VERSION 5.7 ;
BUSBITCHARS "[]" ;
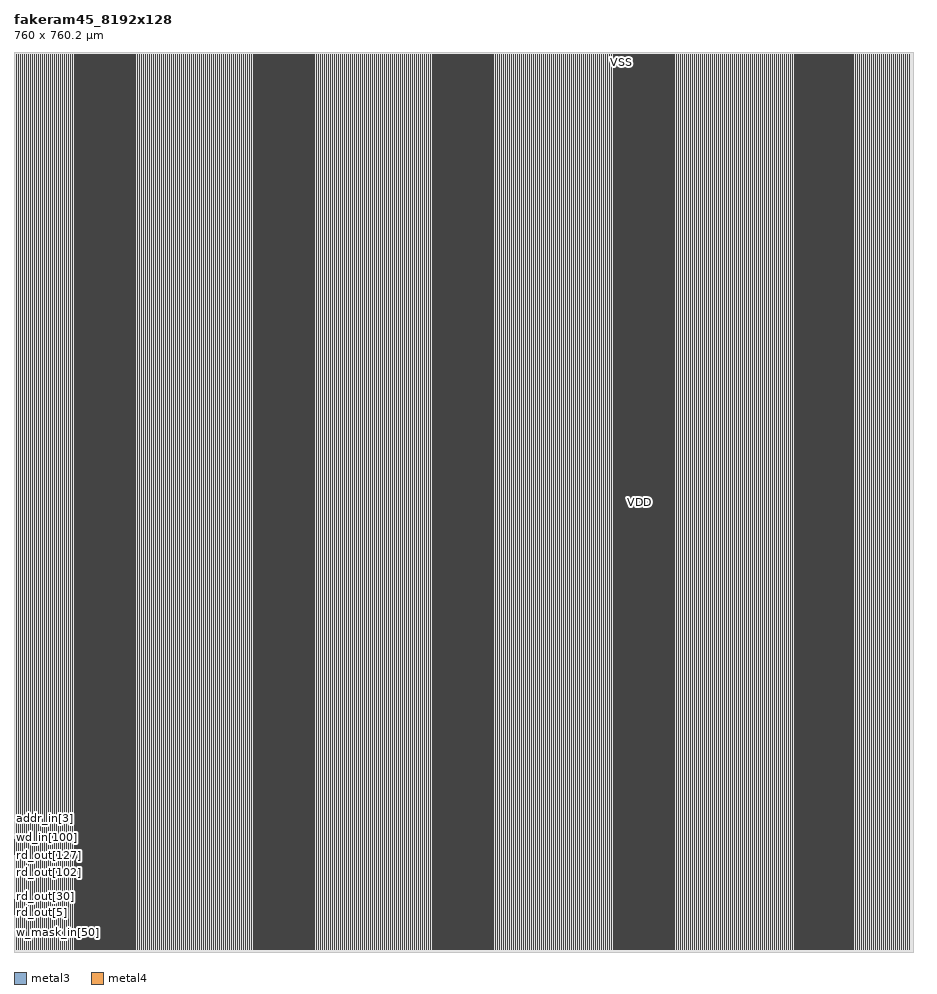
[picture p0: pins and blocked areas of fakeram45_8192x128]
MACRO fakeram45_8192x128
  FOREIGN fakeram45_8192x128 0 0 ;
  SYMMETRY X Y R90 ;
  SIZE 760.000 BY 760.200 ;
  CLASS BLOCK ;
  PIN w_mask_in[0]
    DIRECTION INPUT ;
    USE SIGNAL ;
    SHAPE ABUTMENT ;
    PORT
      LAYER metal3 ;
      RECT 0.000 2.135 0.070 2.205 ;
    END
  END w_mask_in[0]
  PIN w_mask_in[1]
    DIRECTION INPUT ;
    USE SIGNAL ;
    SHAPE ABUTMENT ;
    PORT
      LAYER metal3 ;
      RECT 0.000 2.415 0.070 2.485 ;
    END
  END w_mask_in[1]
  PIN w_mask_in[2]
    DIRECTION INPUT ;
    USE SIGNAL ;
    SHAPE ABUTMENT ;
    PORT
      LAYER metal3 ;
      RECT 0.000 2.695 0.070 2.765 ;
    END
  END w_mask_in[2]
  PIN w_mask_in[3]
    DIRECTION INPUT ;
    USE SIGNAL ;
    SHAPE ABUTMENT ;
    PORT
      LAYER metal3 ;
      RECT 0.000 2.975 0.070 3.045 ;
    END
  END w_mask_in[3]
  PIN w_mask_in[4]
    DIRECTION INPUT ;
    USE SIGNAL ;
    SHAPE ABUTMENT ;
    PORT
      LAYER metal3 ;
      RECT 0.000 3.255 0.070 3.325 ;
    END
  END w_mask_in[4]
  PIN w_mask_in[5]
    DIRECTION INPUT ;
    USE SIGNAL ;
    SHAPE ABUTMENT ;
    PORT
      LAYER metal3 ;
      RECT 0.000 3.535 0.070 3.605 ;
    END
  END w_mask_in[5]
  PIN w_mask_in[6]
    DIRECTION INPUT ;
    USE SIGNAL ;
    SHAPE ABUTMENT ;
    PORT
      LAYER metal3 ;
      RECT 0.000 3.815 0.070 3.885 ;
    END
  END w_mask_in[6]
  PIN w_mask_in[7]
    DIRECTION INPUT ;
    USE SIGNAL ;
    SHAPE ABUTMENT ;
    PORT
      LAYER metal3 ;
      RECT 0.000 4.095 0.070 4.165 ;
    END
  END w_mask_in[7]
  PIN w_mask_in[8]
    DIRECTION INPUT ;
    USE SIGNAL ;
    SHAPE ABUTMENT ;
    PORT
      LAYER metal3 ;
      RECT 0.000 4.375 0.070 4.445 ;
    END
  END w_mask_in[8]
  PIN w_mask_in[9]
    DIRECTION INPUT ;
    USE SIGNAL ;
    SHAPE ABUTMENT ;
    PORT
      LAYER metal3 ;
      RECT 0.000 4.655 0.070 4.725 ;
    END
  END w_mask_in[9]
  PIN w_mask_in[10]
    DIRECTION INPUT ;
    USE SIGNAL ;
    SHAPE ABUTMENT ;
    PORT
      LAYER metal3 ;
      RECT 0.000 4.935 0.070 5.005 ;
    END
  END w_mask_in[10]
  PIN w_mask_in[11]
    DIRECTION INPUT ;
    USE SIGNAL ;
    SHAPE ABUTMENT ;
    PORT
      LAYER metal3 ;
      RECT 0.000 5.215 0.070 5.285 ;
    END
  END w_mask_in[11]
  PIN w_mask_in[12]
    DIRECTION INPUT ;
    USE SIGNAL ;
    SHAPE ABUTMENT ;
    PORT
      LAYER metal3 ;
      RECT 0.000 5.495 0.070 5.565 ;
    END
  END w_mask_in[12]
  PIN w_mask_in[13]
    DIRECTION INPUT ;
    USE SIGNAL ;
    SHAPE ABUTMENT ;
    PORT
      LAYER metal3 ;
      RECT 0.000 5.775 0.070 5.845 ;
    END
  END w_mask_in[13]
  PIN w_mask_in[14]
    DIRECTION INPUT ;
    USE SIGNAL ;
    SHAPE ABUTMENT ;
    PORT
      LAYER metal3 ;
      RECT 0.000 6.055 0.070 6.125 ;
    END
  END w_mask_in[14]
  PIN w_mask_in[15]
    DIRECTION INPUT ;
    USE SIGNAL ;
    SHAPE ABUTMENT ;
    PORT
      LAYER metal3 ;
      RECT 0.000 6.335 0.070 6.405 ;
    END
  END w_mask_in[15]
  PIN w_mask_in[16]
    DIRECTION INPUT ;
    USE SIGNAL ;
    SHAPE ABUTMENT ;
    PORT
      LAYER metal3 ;
      RECT 0.000 6.615 0.070 6.685 ;
    END
  END w_mask_in[16]
  PIN w_mask_in[17]
    DIRECTION INPUT ;
    USE SIGNAL ;
    SHAPE ABUTMENT ;
    PORT
      LAYER metal3 ;
      RECT 0.000 6.895 0.070 6.965 ;
    END
  END w_mask_in[17]
  PIN w_mask_in[18]
    DIRECTION INPUT ;
    USE SIGNAL ;
    SHAPE ABUTMENT ;
    PORT
      LAYER metal3 ;
      RECT 0.000 7.175 0.070 7.245 ;
    END
  END w_mask_in[18]
  PIN w_mask_in[19]
    DIRECTION INPUT ;
    USE SIGNAL ;
    SHAPE ABUTMENT ;
    PORT
      LAYER metal3 ;
      RECT 0.000 7.455 0.070 7.525 ;
    END
  END w_mask_in[19]
  PIN w_mask_in[20]
    DIRECTION INPUT ;
    USE SIGNAL ;
    SHAPE ABUTMENT ;
    PORT
      LAYER metal3 ;
      RECT 0.000 7.735 0.070 7.805 ;
    END
  END w_mask_in[20]
  PIN w_mask_in[21]
    DIRECTION INPUT ;
    USE SIGNAL ;
    SHAPE ABUTMENT ;
    PORT
      LAYER metal3 ;
      RECT 0.000 8.015 0.070 8.085 ;
    END
  END w_mask_in[21]
  PIN w_mask_in[22]
    DIRECTION INPUT ;
    USE SIGNAL ;
    SHAPE ABUTMENT ;
    PORT
      LAYER metal3 ;
      RECT 0.000 8.295 0.070 8.365 ;
    END
  END w_mask_in[22]
  PIN w_mask_in[23]
    DIRECTION INPUT ;
    USE SIGNAL ;
    SHAPE ABUTMENT ;
    PORT
      LAYER metal3 ;
      RECT 0.000 8.575 0.070 8.645 ;
    END
  END w_mask_in[23]
  PIN w_mask_in[24]
    DIRECTION INPUT ;
    USE SIGNAL ;
    SHAPE ABUTMENT ;
    PORT
      LAYER metal3 ;
      RECT 0.000 8.855 0.070 8.925 ;
    END
  END w_mask_in[24]
  PIN w_mask_in[25]
    DIRECTION INPUT ;
    USE SIGNAL ;
    SHAPE ABUTMENT ;
    PORT
      LAYER metal3 ;
      RECT 0.000 9.135 0.070 9.205 ;
    END
  END w_mask_in[25]
  PIN w_mask_in[26]
    DIRECTION INPUT ;
    USE SIGNAL ;
    SHAPE ABUTMENT ;
    PORT
      LAYER metal3 ;
      RECT 0.000 9.415 0.070 9.485 ;
    END
  END w_mask_in[26]
  PIN w_mask_in[27]
    DIRECTION INPUT ;
    USE SIGNAL ;
    SHAPE ABUTMENT ;
    PORT
      LAYER metal3 ;
      RECT 0.000 9.695 0.070 9.765 ;
    END
  END w_mask_in[27]
  PIN w_mask_in[28]
    DIRECTION INPUT ;
    USE SIGNAL ;
    SHAPE ABUTMENT ;
    PORT
      LAYER metal3 ;
      RECT 0.000 9.975 0.070 10.045 ;
    END
  END w_mask_in[28]
  PIN w_mask_in[29]
    DIRECTION INPUT ;
    USE SIGNAL ;
    SHAPE ABUTMENT ;
    PORT
      LAYER metal3 ;
      RECT 0.000 10.255 0.070 10.325 ;
    END
  END w_mask_in[29]
  PIN w_mask_in[30]
    DIRECTION INPUT ;
    USE SIGNAL ;
    SHAPE ABUTMENT ;
    PORT
      LAYER metal3 ;
      RECT 0.000 10.535 0.070 10.605 ;
    END
  END w_mask_in[30]
  PIN w_mask_in[31]
    DIRECTION INPUT ;
    USE SIGNAL ;
    SHAPE ABUTMENT ;
    PORT
      LAYER metal3 ;
      RECT 0.000 10.815 0.070 10.885 ;
    END
  END w_mask_in[31]
  PIN w_mask_in[32]
    DIRECTION INPUT ;
    USE SIGNAL ;
    SHAPE ABUTMENT ;
    PORT
      LAYER metal3 ;
      RECT 0.000 11.095 0.070 11.165 ;
    END
  END w_mask_in[32]
  PIN w_mask_in[33]
    DIRECTION INPUT ;
    USE SIGNAL ;
    SHAPE ABUTMENT ;
    PORT
      LAYER metal3 ;
      RECT 0.000 11.375 0.070 11.445 ;
    END
  END w_mask_in[33]
  PIN w_mask_in[34]
    DIRECTION INPUT ;
    USE SIGNAL ;
    SHAPE ABUTMENT ;
    PORT
      LAYER metal3 ;
      RECT 0.000 11.655 0.070 11.725 ;
    END
  END w_mask_in[34]
  PIN w_mask_in[35]
    DIRECTION INPUT ;
    USE SIGNAL ;
    SHAPE ABUTMENT ;
    PORT
      LAYER metal3 ;
      RECT 0.000 11.935 0.070 12.005 ;
    END
  END w_mask_in[35]
  PIN w_mask_in[36]
    DIRECTION INPUT ;
    USE SIGNAL ;
    SHAPE ABUTMENT ;
    PORT
      LAYER metal3 ;
      RECT 0.000 12.215 0.070 12.285 ;
    END
  END w_mask_in[36]
  PIN w_mask_in[37]
    DIRECTION INPUT ;
    USE SIGNAL ;
    SHAPE ABUTMENT ;
    PORT
      LAYER metal3 ;
      RECT 0.000 12.495 0.070 12.565 ;
    END
  END w_mask_in[37]
  PIN w_mask_in[38]
    DIRECTION INPUT ;
    USE SIGNAL ;
    SHAPE ABUTMENT ;
    PORT
      LAYER metal3 ;
      RECT 0.000 12.775 0.070 12.845 ;
    END
  END w_mask_in[38]
  PIN w_mask_in[39]
    DIRECTION INPUT ;
    USE SIGNAL ;
    SHAPE ABUTMENT ;
    PORT
      LAYER metal3 ;
      RECT 0.000 13.055 0.070 13.125 ;
    END
  END w_mask_in[39]
  PIN w_mask_in[40]
    DIRECTION INPUT ;
    USE SIGNAL ;
    SHAPE ABUTMENT ;
    PORT
      LAYER metal3 ;
      RECT 0.000 13.335 0.070 13.405 ;
    END
  END w_mask_in[40]
  PIN w_mask_in[41]
    DIRECTION INPUT ;
    USE SIGNAL ;
    SHAPE ABUTMENT ;
    PORT
      LAYER metal3 ;
      RECT 0.000 13.615 0.070 13.685 ;
    END
  END w_mask_in[41]
  PIN w_mask_in[42]
    DIRECTION INPUT ;
    USE SIGNAL ;
    SHAPE ABUTMENT ;
    PORT
      LAYER metal3 ;
      RECT 0.000 13.895 0.070 13.965 ;
    END
  END w_mask_in[42]
  PIN w_mask_in[43]
    DIRECTION INPUT ;
    USE SIGNAL ;
    SHAPE ABUTMENT ;
    PORT
      LAYER metal3 ;
      RECT 0.000 14.175 0.070 14.245 ;
    END
  END w_mask_in[43]
  PIN w_mask_in[44]
    DIRECTION INPUT ;
    USE SIGNAL ;
    SHAPE ABUTMENT ;
    PORT
      LAYER metal3 ;
      RECT 0.000 14.455 0.070 14.525 ;
    END
  END w_mask_in[44]
  PIN w_mask_in[45]
    DIRECTION INPUT ;
    USE SIGNAL ;
    SHAPE ABUTMENT ;
    PORT
      LAYER metal3 ;
      RECT 0.000 14.735 0.070 14.805 ;
    END
  END w_mask_in[45]
  PIN w_mask_in[46]
    DIRECTION INPUT ;
    USE SIGNAL ;
    SHAPE ABUTMENT ;
    PORT
      LAYER metal3 ;
      RECT 0.000 15.015 0.070 15.085 ;
    END
  END w_mask_in[46]
  PIN w_mask_in[47]
    DIRECTION INPUT ;
    USE SIGNAL ;
    SHAPE ABUTMENT ;
    PORT
      LAYER metal3 ;
      RECT 0.000 15.295 0.070 15.365 ;
    END
  END w_mask_in[47]
  PIN w_mask_in[48]
    DIRECTION INPUT ;
    USE SIGNAL ;
    SHAPE ABUTMENT ;
    PORT
      LAYER metal3 ;
      RECT 0.000 15.575 0.070 15.645 ;
    END
  END w_mask_in[48]
  PIN w_mask_in[49]
    DIRECTION INPUT ;
    USE SIGNAL ;
    SHAPE ABUTMENT ;
    PORT
      LAYER metal3 ;
      RECT 0.000 15.855 0.070 15.925 ;
    END
  END w_mask_in[49]
  PIN w_mask_in[50]
    DIRECTION INPUT ;
    USE SIGNAL ;
    SHAPE ABUTMENT ;
    PORT
      LAYER metal3 ;
      RECT 0.000 16.135 0.070 16.205 ;
    END
  END w_mask_in[50]
  PIN w_mask_in[51]
    DIRECTION INPUT ;
    USE SIGNAL ;
    SHAPE ABUTMENT ;
    PORT
      LAYER metal3 ;
      RECT 0.000 16.415 0.070 16.485 ;
    END
  END w_mask_in[51]
  PIN w_mask_in[52]
    DIRECTION INPUT ;
    USE SIGNAL ;
    SHAPE ABUTMENT ;
    PORT
      LAYER metal3 ;
      RECT 0.000 16.695 0.070 16.765 ;
    END
  END w_mask_in[52]
  PIN w_mask_in[53]
    DIRECTION INPUT ;
    USE SIGNAL ;
    SHAPE ABUTMENT ;
    PORT
      LAYER metal3 ;
      RECT 0.000 16.975 0.070 17.045 ;
    END
  END w_mask_in[53]
  PIN w_mask_in[54]
    DIRECTION INPUT ;
    USE SIGNAL ;
    SHAPE ABUTMENT ;
    PORT
      LAYER metal3 ;
      RECT 0.000 17.255 0.070 17.325 ;
    END
  END w_mask_in[54]
  PIN w_mask_in[55]
    DIRECTION INPUT ;
    USE SIGNAL ;
    SHAPE ABUTMENT ;
    PORT
      LAYER metal3 ;
      RECT 0.000 17.535 0.070 17.605 ;
    END
  END w_mask_in[55]
  PIN w_mask_in[56]
    DIRECTION INPUT ;
    USE SIGNAL ;
    SHAPE ABUTMENT ;
    PORT
      LAYER metal3 ;
      RECT 0.000 17.815 0.070 17.885 ;
    END
  END w_mask_in[56]
  PIN w_mask_in[57]
    DIRECTION INPUT ;
    USE SIGNAL ;
    SHAPE ABUTMENT ;
    PORT
      LAYER metal3 ;
      RECT 0.000 18.095 0.070 18.165 ;
    END
  END w_mask_in[57]
  PIN w_mask_in[58]
    DIRECTION INPUT ;
    USE SIGNAL ;
    SHAPE ABUTMENT ;
    PORT
      LAYER metal3 ;
      RECT 0.000 18.375 0.070 18.445 ;
    END
  END w_mask_in[58]
  PIN w_mask_in[59]
    DIRECTION INPUT ;
    USE SIGNAL ;
    SHAPE ABUTMENT ;
    PORT
      LAYER metal3 ;
      RECT 0.000 18.655 0.070 18.725 ;
    END
  END w_mask_in[59]
  PIN w_mask_in[60]
    DIRECTION INPUT ;
    USE SIGNAL ;
    SHAPE ABUTMENT ;
    PORT
      LAYER metal3 ;
      RECT 0.000 18.935 0.070 19.005 ;
    END
  END w_mask_in[60]
  PIN w_mask_in[61]
    DIRECTION INPUT ;
    USE SIGNAL ;
    SHAPE ABUTMENT ;
    PORT
      LAYER metal3 ;
      RECT 0.000 19.215 0.070 19.285 ;
    END
  END w_mask_in[61]
  PIN w_mask_in[62]
    DIRECTION INPUT ;
    USE SIGNAL ;
    SHAPE ABUTMENT ;
    PORT
      LAYER metal3 ;
      RECT 0.000 19.495 0.070 19.565 ;
    END
  END w_mask_in[62]
  PIN w_mask_in[63]
    DIRECTION INPUT ;
    USE SIGNAL ;
    SHAPE ABUTMENT ;
    PORT
      LAYER metal3 ;
      RECT 0.000 19.775 0.070 19.845 ;
    END
  END w_mask_in[63]
  PIN w_mask_in[64]
    DIRECTION INPUT ;
    USE SIGNAL ;
    SHAPE ABUTMENT ;
    PORT
      LAYER metal3 ;
      RECT 0.000 20.055 0.070 20.125 ;
    END
  END w_mask_in[64]
  PIN w_mask_in[65]
    DIRECTION INPUT ;
    USE SIGNAL ;
    SHAPE ABUTMENT ;
    PORT
      LAYER metal3 ;
      RECT 0.000 20.335 0.070 20.405 ;
    END
  END w_mask_in[65]
  PIN w_mask_in[66]
    DIRECTION INPUT ;
    USE SIGNAL ;
    SHAPE ABUTMENT ;
    PORT
      LAYER metal3 ;
      RECT 0.000 20.615 0.070 20.685 ;
    END
  END w_mask_in[66]
  PIN w_mask_in[67]
    DIRECTION INPUT ;
    USE SIGNAL ;
    SHAPE ABUTMENT ;
    PORT
      LAYER metal3 ;
      RECT 0.000 20.895 0.070 20.965 ;
    END
  END w_mask_in[67]
  PIN w_mask_in[68]
    DIRECTION INPUT ;
    USE SIGNAL ;
    SHAPE ABUTMENT ;
    PORT
      LAYER metal3 ;
      RECT 0.000 21.175 0.070 21.245 ;
    END
  END w_mask_in[68]
  PIN w_mask_in[69]
    DIRECTION INPUT ;
    USE SIGNAL ;
    SHAPE ABUTMENT ;
    PORT
      LAYER metal3 ;
      RECT 0.000 21.455 0.070 21.525 ;
    END
  END w_mask_in[69]
  PIN w_mask_in[70]
    DIRECTION INPUT ;
    USE SIGNAL ;
    SHAPE ABUTMENT ;
    PORT
      LAYER metal3 ;
      RECT 0.000 21.735 0.070 21.805 ;
    END
  END w_mask_in[70]
  PIN w_mask_in[71]
    DIRECTION INPUT ;
    USE SIGNAL ;
    SHAPE ABUTMENT ;
    PORT
      LAYER metal3 ;
      RECT 0.000 22.015 0.070 22.085 ;
    END
  END w_mask_in[71]
  PIN w_mask_in[72]
    DIRECTION INPUT ;
    USE SIGNAL ;
    SHAPE ABUTMENT ;
    PORT
      LAYER metal3 ;
      RECT 0.000 22.295 0.070 22.365 ;
    END
  END w_mask_in[72]
  PIN w_mask_in[73]
    DIRECTION INPUT ;
    USE SIGNAL ;
    SHAPE ABUTMENT ;
    PORT
      LAYER metal3 ;
      RECT 0.000 22.575 0.070 22.645 ;
    END
  END w_mask_in[73]
  PIN w_mask_in[74]
    DIRECTION INPUT ;
    USE SIGNAL ;
    SHAPE ABUTMENT ;
    PORT
      LAYER metal3 ;
      RECT 0.000 22.855 0.070 22.925 ;
    END
  END w_mask_in[74]
  PIN w_mask_in[75]
    DIRECTION INPUT ;
    USE SIGNAL ;
    SHAPE ABUTMENT ;
    PORT
      LAYER metal3 ;
      RECT 0.000 23.135 0.070 23.205 ;
    END
  END w_mask_in[75]
  PIN w_mask_in[76]
    DIRECTION INPUT ;
    USE SIGNAL ;
    SHAPE ABUTMENT ;
    PORT
      LAYER metal3 ;
      RECT 0.000 23.415 0.070 23.485 ;
    END
  END w_mask_in[76]
  PIN w_mask_in[77]
    DIRECTION INPUT ;
    USE SIGNAL ;
    SHAPE ABUTMENT ;
    PORT
      LAYER metal3 ;
      RECT 0.000 23.695 0.070 23.765 ;
    END
  END w_mask_in[77]
  PIN w_mask_in[78]
    DIRECTION INPUT ;
    USE SIGNAL ;
    SHAPE ABUTMENT ;
    PORT
      LAYER metal3 ;
      RECT 0.000 23.975 0.070 24.045 ;
    END
  END w_mask_in[78]
  PIN w_mask_in[79]
    DIRECTION INPUT ;
    USE SIGNAL ;
    SHAPE ABUTMENT ;
    PORT
      LAYER metal3 ;
      RECT 0.000 24.255 0.070 24.325 ;
    END
  END w_mask_in[79]
  PIN w_mask_in[80]
    DIRECTION INPUT ;
    USE SIGNAL ;
    SHAPE ABUTMENT ;
    PORT
      LAYER metal3 ;
      RECT 0.000 24.535 0.070 24.605 ;
    END
  END w_mask_in[80]
  PIN w_mask_in[81]
    DIRECTION INPUT ;
    USE SIGNAL ;
    SHAPE ABUTMENT ;
    PORT
      LAYER metal3 ;
      RECT 0.000 24.815 0.070 24.885 ;
    END
  END w_mask_in[81]
  PIN w_mask_in[82]
    DIRECTION INPUT ;
    USE SIGNAL ;
    SHAPE ABUTMENT ;
    PORT
      LAYER metal3 ;
      RECT 0.000 25.095 0.070 25.165 ;
    END
  END w_mask_in[82]
  PIN w_mask_in[83]
    DIRECTION INPUT ;
    USE SIGNAL ;
    SHAPE ABUTMENT ;
    PORT
      LAYER metal3 ;
      RECT 0.000 25.375 0.070 25.445 ;
    END
  END w_mask_in[83]
  PIN w_mask_in[84]
    DIRECTION INPUT ;
    USE SIGNAL ;
    SHAPE ABUTMENT ;
    PORT
      LAYER metal3 ;
      RECT 0.000 25.655 0.070 25.725 ;
    END
  END w_mask_in[84]
  PIN w_mask_in[85]
    DIRECTION INPUT ;
    USE SIGNAL ;
    SHAPE ABUTMENT ;
    PORT
      LAYER metal3 ;
      RECT 0.000 25.935 0.070 26.005 ;
    END
  END w_mask_in[85]
  PIN w_mask_in[86]
    DIRECTION INPUT ;
    USE SIGNAL ;
    SHAPE ABUTMENT ;
    PORT
      LAYER metal3 ;
      RECT 0.000 26.215 0.070 26.285 ;
    END
  END w_mask_in[86]
  PIN w_mask_in[87]
    DIRECTION INPUT ;
    USE SIGNAL ;
    SHAPE ABUTMENT ;
    PORT
      LAYER metal3 ;
      RECT 0.000 26.495 0.070 26.565 ;
    END
  END w_mask_in[87]
  PIN w_mask_in[88]
    DIRECTION INPUT ;
    USE SIGNAL ;
    SHAPE ABUTMENT ;
    PORT
      LAYER metal3 ;
      RECT 0.000 26.775 0.070 26.845 ;
    END
  END w_mask_in[88]
  PIN w_mask_in[89]
    DIRECTION INPUT ;
    USE SIGNAL ;
    SHAPE ABUTMENT ;
    PORT
      LAYER metal3 ;
      RECT 0.000 27.055 0.070 27.125 ;
    END
  END w_mask_in[89]
  PIN w_mask_in[90]
    DIRECTION INPUT ;
    USE SIGNAL ;
    SHAPE ABUTMENT ;
    PORT
      LAYER metal3 ;
      RECT 0.000 27.335 0.070 27.405 ;
    END
  END w_mask_in[90]
  PIN w_mask_in[91]
    DIRECTION INPUT ;
    USE SIGNAL ;
    SHAPE ABUTMENT ;
    PORT
      LAYER metal3 ;
      RECT 0.000 27.615 0.070 27.685 ;
    END
  END w_mask_in[91]
  PIN w_mask_in[92]
    DIRECTION INPUT ;
    USE SIGNAL ;
    SHAPE ABUTMENT ;
    PORT
      LAYER metal3 ;
      RECT 0.000 27.895 0.070 27.965 ;
    END
  END w_mask_in[92]
  PIN w_mask_in[93]
    DIRECTION INPUT ;
    USE SIGNAL ;
    SHAPE ABUTMENT ;
    PORT
      LAYER metal3 ;
      RECT 0.000 28.175 0.070 28.245 ;
    END
  END w_mask_in[93]
  PIN w_mask_in[94]
    DIRECTION INPUT ;
    USE SIGNAL ;
    SHAPE ABUTMENT ;
    PORT
      LAYER metal3 ;
      RECT 0.000 28.455 0.070 28.525 ;
    END
  END w_mask_in[94]
  PIN w_mask_in[95]
    DIRECTION INPUT ;
    USE SIGNAL ;
    SHAPE ABUTMENT ;
    PORT
      LAYER metal3 ;
      RECT 0.000 28.735 0.070 28.805 ;
    END
  END w_mask_in[95]
  PIN w_mask_in[96]
    DIRECTION INPUT ;
    USE SIGNAL ;
    SHAPE ABUTMENT ;
    PORT
      LAYER metal3 ;
      RECT 0.000 29.015 0.070 29.085 ;
    END
  END w_mask_in[96]
  PIN w_mask_in[97]
    DIRECTION INPUT ;
    USE SIGNAL ;
    SHAPE ABUTMENT ;
    PORT
      LAYER metal3 ;
      RECT 0.000 29.295 0.070 29.365 ;
    END
  END w_mask_in[97]
  PIN w_mask_in[98]
    DIRECTION INPUT ;
    USE SIGNAL ;
    SHAPE ABUTMENT ;
    PORT
      LAYER metal3 ;
      RECT 0.000 29.575 0.070 29.645 ;
    END
  END w_mask_in[98]
  PIN w_mask_in[99]
    DIRECTION INPUT ;
    USE SIGNAL ;
    SHAPE ABUTMENT ;
    PORT
      LAYER metal3 ;
      RECT 0.000 29.855 0.070 29.925 ;
    END
  END w_mask_in[99]
  PIN w_mask_in[100]
    DIRECTION INPUT ;
    USE SIGNAL ;
    SHAPE ABUTMENT ;
    PORT
      LAYER metal3 ;
      RECT 0.000 30.135 0.070 30.205 ;
    END
  END w_mask_in[100]
  PIN w_mask_in[101]
    DIRECTION INPUT ;
    USE SIGNAL ;
    SHAPE ABUTMENT ;
    PORT
      LAYER metal3 ;
      RECT 0.000 30.415 0.070 30.485 ;
    END
  END w_mask_in[101]
  PIN w_mask_in[102]
    DIRECTION INPUT ;
    USE SIGNAL ;
    SHAPE ABUTMENT ;
    PORT
      LAYER metal3 ;
      RECT 0.000 30.695 0.070 30.765 ;
    END
  END w_mask_in[102]
  PIN w_mask_in[103]
    DIRECTION INPUT ;
    USE SIGNAL ;
    SHAPE ABUTMENT ;
    PORT
      LAYER metal3 ;
      RECT 0.000 30.975 0.070 31.045 ;
    END
  END w_mask_in[103]
  PIN w_mask_in[104]
    DIRECTION INPUT ;
    USE SIGNAL ;
    SHAPE ABUTMENT ;
    PORT
      LAYER metal3 ;
      RECT 0.000 31.255 0.070 31.325 ;
    END
  END w_mask_in[104]
  PIN w_mask_in[105]
    DIRECTION INPUT ;
    USE SIGNAL ;
    SHAPE ABUTMENT ;
    PORT
      LAYER metal3 ;
      RECT 0.000 31.535 0.070 31.605 ;
    END
  END w_mask_in[105]
  PIN w_mask_in[106]
    DIRECTION INPUT ;
    USE SIGNAL ;
    SHAPE ABUTMENT ;
    PORT
      LAYER metal3 ;
      RECT 0.000 31.815 0.070 31.885 ;
    END
  END w_mask_in[106]
  PIN w_mask_in[107]
    DIRECTION INPUT ;
    USE SIGNAL ;
    SHAPE ABUTMENT ;
    PORT
      LAYER metal3 ;
      RECT 0.000 32.095 0.070 32.165 ;
    END
  END w_mask_in[107]
  PIN w_mask_in[108]
    DIRECTION INPUT ;
    USE SIGNAL ;
    SHAPE ABUTMENT ;
    PORT
      LAYER metal3 ;
      RECT 0.000 32.375 0.070 32.445 ;
    END
  END w_mask_in[108]
  PIN w_mask_in[109]
    DIRECTION INPUT ;
    USE SIGNAL ;
    SHAPE ABUTMENT ;
    PORT
      LAYER metal3 ;
      RECT 0.000 32.655 0.070 32.725 ;
    END
  END w_mask_in[109]
  PIN w_mask_in[110]
    DIRECTION INPUT ;
    USE SIGNAL ;
    SHAPE ABUTMENT ;
    PORT
      LAYER metal3 ;
      RECT 0.000 32.935 0.070 33.005 ;
    END
  END w_mask_in[110]
  PIN w_mask_in[111]
    DIRECTION INPUT ;
    USE SIGNAL ;
    SHAPE ABUTMENT ;
    PORT
      LAYER metal3 ;
      RECT 0.000 33.215 0.070 33.285 ;
    END
  END w_mask_in[111]
  PIN w_mask_in[112]
    DIRECTION INPUT ;
    USE SIGNAL ;
    SHAPE ABUTMENT ;
    PORT
      LAYER metal3 ;
      RECT 0.000 33.495 0.070 33.565 ;
    END
  END w_mask_in[112]
  PIN w_mask_in[113]
    DIRECTION INPUT ;
    USE SIGNAL ;
    SHAPE ABUTMENT ;
    PORT
      LAYER metal3 ;
      RECT 0.000 33.775 0.070 33.845 ;
    END
  END w_mask_in[113]
  PIN w_mask_in[114]
    DIRECTION INPUT ;
    USE SIGNAL ;
    SHAPE ABUTMENT ;
    PORT
      LAYER metal3 ;
      RECT 0.000 34.055 0.070 34.125 ;
    END
  END w_mask_in[114]
  PIN w_mask_in[115]
    DIRECTION INPUT ;
    USE SIGNAL ;
    SHAPE ABUTMENT ;
    PORT
      LAYER metal3 ;
      RECT 0.000 34.335 0.070 34.405 ;
    END
  END w_mask_in[115]
  PIN w_mask_in[116]
    DIRECTION INPUT ;
    USE SIGNAL ;
    SHAPE ABUTMENT ;
    PORT
      LAYER metal3 ;
      RECT 0.000 34.615 0.070 34.685 ;
    END
  END w_mask_in[116]
  PIN w_mask_in[117]
    DIRECTION INPUT ;
    USE SIGNAL ;
    SHAPE ABUTMENT ;
    PORT
      LAYER metal3 ;
      RECT 0.000 34.895 0.070 34.965 ;
    END
  END w_mask_in[117]
  PIN w_mask_in[118]
    DIRECTION INPUT ;
    USE SIGNAL ;
    SHAPE ABUTMENT ;
    PORT
      LAYER metal3 ;
      RECT 0.000 35.175 0.070 35.245 ;
    END
  END w_mask_in[118]
  PIN w_mask_in[119]
    DIRECTION INPUT ;
    USE SIGNAL ;
    SHAPE ABUTMENT ;
    PORT
      LAYER metal3 ;
      RECT 0.000 35.455 0.070 35.525 ;
    END
  END w_mask_in[119]
  PIN w_mask_in[120]
    DIRECTION INPUT ;
    USE SIGNAL ;
    SHAPE ABUTMENT ;
    PORT
      LAYER metal3 ;
      RECT 0.000 35.735 0.070 35.805 ;
    END
  END w_mask_in[120]
  PIN w_mask_in[121]
    DIRECTION INPUT ;
    USE SIGNAL ;
    SHAPE ABUTMENT ;
    PORT
      LAYER metal3 ;
      RECT 0.000 36.015 0.070 36.085 ;
    END
  END w_mask_in[121]
  PIN w_mask_in[122]
    DIRECTION INPUT ;
    USE SIGNAL ;
    SHAPE ABUTMENT ;
    PORT
      LAYER metal3 ;
      RECT 0.000 36.295 0.070 36.365 ;
    END
  END w_mask_in[122]
  PIN w_mask_in[123]
    DIRECTION INPUT ;
    USE SIGNAL ;
    SHAPE ABUTMENT ;
    PORT
      LAYER metal3 ;
      RECT 0.000 36.575 0.070 36.645 ;
    END
  END w_mask_in[123]
  PIN w_mask_in[124]
    DIRECTION INPUT ;
    USE SIGNAL ;
    SHAPE ABUTMENT ;
    PORT
      LAYER metal3 ;
      RECT 0.000 36.855 0.070 36.925 ;
    END
  END w_mask_in[124]
  PIN w_mask_in[125]
    DIRECTION INPUT ;
    USE SIGNAL ;
    SHAPE ABUTMENT ;
    PORT
      LAYER metal3 ;
      RECT 0.000 37.135 0.070 37.205 ;
    END
  END w_mask_in[125]
  PIN w_mask_in[126]
    DIRECTION INPUT ;
    USE SIGNAL ;
    SHAPE ABUTMENT ;
    PORT
      LAYER metal3 ;
      RECT 0.000 37.415 0.070 37.485 ;
    END
  END w_mask_in[126]
  PIN w_mask_in[127]
    DIRECTION INPUT ;
    USE SIGNAL ;
    SHAPE ABUTMENT ;
    PORT
      LAYER metal3 ;
      RECT 0.000 37.695 0.070 37.765 ;
    END
  END w_mask_in[127]
  PIN rd_out[0]
    DIRECTION OUTPUT ;
    USE SIGNAL ;
    SHAPE ABUTMENT ;
    PORT
      LAYER metal3 ;
      RECT 0.000 38.815 0.070 38.885 ;
    END
  END rd_out[0]
  PIN rd_out[1]
    DIRECTION OUTPUT ;
    USE SIGNAL ;
    SHAPE ABUTMENT ;
    PORT
      LAYER metal3 ;
      RECT 0.000 39.095 0.070 39.165 ;
    END
  END rd_out[1]
  PIN rd_out[2]
    DIRECTION OUTPUT ;
    USE SIGNAL ;
    SHAPE ABUTMENT ;
    PORT
      LAYER metal3 ;
      RECT 0.000 39.375 0.070 39.445 ;
    END
  END rd_out[2]
  PIN rd_out[3]
    DIRECTION OUTPUT ;
    USE SIGNAL ;
    SHAPE ABUTMENT ;
    PORT
      LAYER metal3 ;
      RECT 0.000 39.655 0.070 39.725 ;
    END
  END rd_out[3]
  PIN rd_out[4]
    DIRECTION OUTPUT ;
    USE SIGNAL ;
    SHAPE ABUTMENT ;
    PORT
      LAYER metal3 ;
      RECT 0.000 39.935 0.070 40.005 ;
    END
  END rd_out[4]
  PIN rd_out[5]
    DIRECTION OUTPUT ;
    USE SIGNAL ;
    SHAPE ABUTMENT ;
    PORT
      LAYER metal3 ;
      RECT 0.000 40.215 0.070 40.285 ;
    END
  END rd_out[5]
  PIN rd_out[6]
    DIRECTION OUTPUT ;
    USE SIGNAL ;
    SHAPE ABUTMENT ;
    PORT
      LAYER metal3 ;
      RECT 0.000 40.495 0.070 40.565 ;
    END
  END rd_out[6]
  PIN rd_out[7]
    DIRECTION OUTPUT ;
    USE SIGNAL ;
    SHAPE ABUTMENT ;
    PORT
      LAYER metal3 ;
      RECT 0.000 40.775 0.070 40.845 ;
    END
  END rd_out[7]
  PIN rd_out[8]
    DIRECTION OUTPUT ;
    USE SIGNAL ;
    SHAPE ABUTMENT ;
    PORT
      LAYER metal3 ;
      RECT 0.000 41.055 0.070 41.125 ;
    END
  END rd_out[8]
  PIN rd_out[9]
    DIRECTION OUTPUT ;
    USE SIGNAL ;
    SHAPE ABUTMENT ;
    PORT
      LAYER metal3 ;
      RECT 0.000 41.335 0.070 41.405 ;
    END
  END rd_out[9]
  PIN rd_out[10]
    DIRECTION OUTPUT ;
    USE SIGNAL ;
    SHAPE ABUTMENT ;
    PORT
      LAYER metal3 ;
      RECT 0.000 41.615 0.070 41.685 ;
    END
  END rd_out[10]
  PIN rd_out[11]
    DIRECTION OUTPUT ;
    USE SIGNAL ;
    SHAPE ABUTMENT ;
    PORT
      LAYER metal3 ;
      RECT 0.000 41.895 0.070 41.965 ;
    END
  END rd_out[11]
  PIN rd_out[12]
    DIRECTION OUTPUT ;
    USE SIGNAL ;
    SHAPE ABUTMENT ;
    PORT
      LAYER metal3 ;
      RECT 0.000 42.175 0.070 42.245 ;
    END
  END rd_out[12]
  PIN rd_out[13]
    DIRECTION OUTPUT ;
    USE SIGNAL ;
    SHAPE ABUTMENT ;
    PORT
      LAYER metal3 ;
      RECT 0.000 42.455 0.070 42.525 ;
    END
  END rd_out[13]
  PIN rd_out[14]
    DIRECTION OUTPUT ;
    USE SIGNAL ;
    SHAPE ABUTMENT ;
    PORT
      LAYER metal3 ;
      RECT 0.000 42.735 0.070 42.805 ;
    END
  END rd_out[14]
  PIN rd_out[15]
    DIRECTION OUTPUT ;
    USE SIGNAL ;
    SHAPE ABUTMENT ;
    PORT
      LAYER metal3 ;
      RECT 0.000 43.015 0.070 43.085 ;
    END
  END rd_out[15]
  PIN rd_out[16]
    DIRECTION OUTPUT ;
    USE SIGNAL ;
    SHAPE ABUTMENT ;
    PORT
      LAYER metal3 ;
      RECT 0.000 43.295 0.070 43.365 ;
    END
  END rd_out[16]
  PIN rd_out[17]
    DIRECTION OUTPUT ;
    USE SIGNAL ;
    SHAPE ABUTMENT ;
    PORT
      LAYER metal3 ;
      RECT 0.000 43.575 0.070 43.645 ;
    END
  END rd_out[17]
  PIN rd_out[18]
    DIRECTION OUTPUT ;
    USE SIGNAL ;
    SHAPE ABUTMENT ;
    PORT
      LAYER metal3 ;
      RECT 0.000 43.855 0.070 43.925 ;
    END
  END rd_out[18]
  PIN rd_out[19]
    DIRECTION OUTPUT ;
    USE SIGNAL ;
    SHAPE ABUTMENT ;
    PORT
      LAYER metal3 ;
      RECT 0.000 44.135 0.070 44.205 ;
    END
  END rd_out[19]
  PIN rd_out[20]
    DIRECTION OUTPUT ;
    USE SIGNAL ;
    SHAPE ABUTMENT ;
    PORT
      LAYER metal3 ;
      RECT 0.000 44.415 0.070 44.485 ;
    END
  END rd_out[20]
  PIN rd_out[21]
    DIRECTION OUTPUT ;
    USE SIGNAL ;
    SHAPE ABUTMENT ;
    PORT
      LAYER metal3 ;
      RECT 0.000 44.695 0.070 44.765 ;
    END
  END rd_out[21]
  PIN rd_out[22]
    DIRECTION OUTPUT ;
    USE SIGNAL ;
    SHAPE ABUTMENT ;
    PORT
      LAYER metal3 ;
      RECT 0.000 44.975 0.070 45.045 ;
    END
  END rd_out[22]
  PIN rd_out[23]
    DIRECTION OUTPUT ;
    USE SIGNAL ;
    SHAPE ABUTMENT ;
    PORT
      LAYER metal3 ;
      RECT 0.000 45.255 0.070 45.325 ;
    END
  END rd_out[23]
  PIN rd_out[24]
    DIRECTION OUTPUT ;
    USE SIGNAL ;
    SHAPE ABUTMENT ;
    PORT
      LAYER metal3 ;
      RECT 0.000 45.535 0.070 45.605 ;
    END
  END rd_out[24]
  PIN rd_out[25]
    DIRECTION OUTPUT ;
    USE SIGNAL ;
    SHAPE ABUTMENT ;
    PORT
      LAYER metal3 ;
      RECT 0.000 45.815 0.070 45.885 ;
    END
  END rd_out[25]
  PIN rd_out[26]
    DIRECTION OUTPUT ;
    USE SIGNAL ;
    SHAPE ABUTMENT ;
    PORT
      LAYER metal3 ;
      RECT 0.000 46.095 0.070 46.165 ;
    END
  END rd_out[26]
  PIN rd_out[27]
    DIRECTION OUTPUT ;
    USE SIGNAL ;
    SHAPE ABUTMENT ;
    PORT
      LAYER metal3 ;
      RECT 0.000 46.375 0.070 46.445 ;
    END
  END rd_out[27]
  PIN rd_out[28]
    DIRECTION OUTPUT ;
    USE SIGNAL ;
    SHAPE ABUTMENT ;
    PORT
      LAYER metal3 ;
      RECT 0.000 46.655 0.070 46.725 ;
    END
  END rd_out[28]
  PIN rd_out[29]
    DIRECTION OUTPUT ;
    USE SIGNAL ;
    SHAPE ABUTMENT ;
    PORT
      LAYER metal3 ;
      RECT 0.000 46.935 0.070 47.005 ;
    END
  END rd_out[29]
  PIN rd_out[30]
    DIRECTION OUTPUT ;
    USE SIGNAL ;
    SHAPE ABUTMENT ;
    PORT
      LAYER metal3 ;
      RECT 0.000 47.215 0.070 47.285 ;
    END
  END rd_out[30]
  PIN rd_out[31]
    DIRECTION OUTPUT ;
    USE SIGNAL ;
    SHAPE ABUTMENT ;
    PORT
      LAYER metal3 ;
      RECT 0.000 47.495 0.070 47.565 ;
    END
  END rd_out[31]
  PIN rd_out[32]
    DIRECTION OUTPUT ;
    USE SIGNAL ;
    SHAPE ABUTMENT ;
    PORT
      LAYER metal3 ;
      RECT 0.000 47.775 0.070 47.845 ;
    END
  END rd_out[32]
  PIN rd_out[33]
    DIRECTION OUTPUT ;
    USE SIGNAL ;
    SHAPE ABUTMENT ;
    PORT
      LAYER metal3 ;
      RECT 0.000 48.055 0.070 48.125 ;
    END
  END rd_out[33]
  PIN rd_out[34]
    DIRECTION OUTPUT ;
    USE SIGNAL ;
    SHAPE ABUTMENT ;
    PORT
      LAYER metal3 ;
      RECT 0.000 48.335 0.070 48.405 ;
    END
  END rd_out[34]
  PIN rd_out[35]
    DIRECTION OUTPUT ;
    USE SIGNAL ;
    SHAPE ABUTMENT ;
    PORT
      LAYER metal3 ;
      RECT 0.000 48.615 0.070 48.685 ;
    END
  END rd_out[35]
  PIN rd_out[36]
    DIRECTION OUTPUT ;
    USE SIGNAL ;
    SHAPE ABUTMENT ;
    PORT
      LAYER metal3 ;
      RECT 0.000 48.895 0.070 48.965 ;
    END
  END rd_out[36]
  PIN rd_out[37]
    DIRECTION OUTPUT ;
    USE SIGNAL ;
    SHAPE ABUTMENT ;
    PORT
      LAYER metal3 ;
      RECT 0.000 49.175 0.070 49.245 ;
    END
  END rd_out[37]
  PIN rd_out[38]
    DIRECTION OUTPUT ;
    USE SIGNAL ;
    SHAPE ABUTMENT ;
    PORT
      LAYER metal3 ;
      RECT 0.000 49.455 0.070 49.525 ;
    END
  END rd_out[38]
  PIN rd_out[39]
    DIRECTION OUTPUT ;
    USE SIGNAL ;
    SHAPE ABUTMENT ;
    PORT
      LAYER metal3 ;
      RECT 0.000 49.735 0.070 49.805 ;
    END
  END rd_out[39]
  PIN rd_out[40]
    DIRECTION OUTPUT ;
    USE SIGNAL ;
    SHAPE ABUTMENT ;
    PORT
      LAYER metal3 ;
      RECT 0.000 50.015 0.070 50.085 ;
    END
  END rd_out[40]
  PIN rd_out[41]
    DIRECTION OUTPUT ;
    USE SIGNAL ;
    SHAPE ABUTMENT ;
    PORT
      LAYER metal3 ;
      RECT 0.000 50.295 0.070 50.365 ;
    END
  END rd_out[41]
  PIN rd_out[42]
    DIRECTION OUTPUT ;
    USE SIGNAL ;
    SHAPE ABUTMENT ;
    PORT
      LAYER metal3 ;
      RECT 0.000 50.575 0.070 50.645 ;
    END
  END rd_out[42]
  PIN rd_out[43]
    DIRECTION OUTPUT ;
    USE SIGNAL ;
    SHAPE ABUTMENT ;
    PORT
      LAYER metal3 ;
      RECT 0.000 50.855 0.070 50.925 ;
    END
  END rd_out[43]
  PIN rd_out[44]
    DIRECTION OUTPUT ;
    USE SIGNAL ;
    SHAPE ABUTMENT ;
    PORT
      LAYER metal3 ;
      RECT 0.000 51.135 0.070 51.205 ;
    END
  END rd_out[44]
  PIN rd_out[45]
    DIRECTION OUTPUT ;
    USE SIGNAL ;
    SHAPE ABUTMENT ;
    PORT
      LAYER metal3 ;
      RECT 0.000 51.415 0.070 51.485 ;
    END
  END rd_out[45]
  PIN rd_out[46]
    DIRECTION OUTPUT ;
    USE SIGNAL ;
    SHAPE ABUTMENT ;
    PORT
      LAYER metal3 ;
      RECT 0.000 51.695 0.070 51.765 ;
    END
  END rd_out[46]
  PIN rd_out[47]
    DIRECTION OUTPUT ;
    USE SIGNAL ;
    SHAPE ABUTMENT ;
    PORT
      LAYER metal3 ;
      RECT 0.000 51.975 0.070 52.045 ;
    END
  END rd_out[47]
  PIN rd_out[48]
    DIRECTION OUTPUT ;
    USE SIGNAL ;
    SHAPE ABUTMENT ;
    PORT
      LAYER metal3 ;
      RECT 0.000 52.255 0.070 52.325 ;
    END
  END rd_out[48]
  PIN rd_out[49]
    DIRECTION OUTPUT ;
    USE SIGNAL ;
    SHAPE ABUTMENT ;
    PORT
      LAYER metal3 ;
      RECT 0.000 52.535 0.070 52.605 ;
    END
  END rd_out[49]
  PIN rd_out[50]
    DIRECTION OUTPUT ;
    USE SIGNAL ;
    SHAPE ABUTMENT ;
    PORT
      LAYER metal3 ;
      RECT 0.000 52.815 0.070 52.885 ;
    END
  END rd_out[50]
  PIN rd_out[51]
    DIRECTION OUTPUT ;
    USE SIGNAL ;
    SHAPE ABUTMENT ;
    PORT
      LAYER metal3 ;
      RECT 0.000 53.095 0.070 53.165 ;
    END
  END rd_out[51]
  PIN rd_out[52]
    DIRECTION OUTPUT ;
    USE SIGNAL ;
    SHAPE ABUTMENT ;
    PORT
      LAYER metal3 ;
      RECT 0.000 53.375 0.070 53.445 ;
    END
  END rd_out[52]
  PIN rd_out[53]
    DIRECTION OUTPUT ;
    USE SIGNAL ;
    SHAPE ABUTMENT ;
    PORT
      LAYER metal3 ;
      RECT 0.000 53.655 0.070 53.725 ;
    END
  END rd_out[53]
  PIN rd_out[54]
    DIRECTION OUTPUT ;
    USE SIGNAL ;
    SHAPE ABUTMENT ;
    PORT
      LAYER metal3 ;
      RECT 0.000 53.935 0.070 54.005 ;
    END
  END rd_out[54]
  PIN rd_out[55]
    DIRECTION OUTPUT ;
    USE SIGNAL ;
    SHAPE ABUTMENT ;
    PORT
      LAYER metal3 ;
      RECT 0.000 54.215 0.070 54.285 ;
    END
  END rd_out[55]
  PIN rd_out[56]
    DIRECTION OUTPUT ;
    USE SIGNAL ;
    SHAPE ABUTMENT ;
    PORT
      LAYER metal3 ;
      RECT 0.000 54.495 0.070 54.565 ;
    END
  END rd_out[56]
  PIN rd_out[57]
    DIRECTION OUTPUT ;
    USE SIGNAL ;
    SHAPE ABUTMENT ;
    PORT
      LAYER metal3 ;
      RECT 0.000 54.775 0.070 54.845 ;
    END
  END rd_out[57]
  PIN rd_out[58]
    DIRECTION OUTPUT ;
    USE SIGNAL ;
    SHAPE ABUTMENT ;
    PORT
      LAYER metal3 ;
      RECT 0.000 55.055 0.070 55.125 ;
    END
  END rd_out[58]
  PIN rd_out[59]
    DIRECTION OUTPUT ;
    USE SIGNAL ;
    SHAPE ABUTMENT ;
    PORT
      LAYER metal3 ;
      RECT 0.000 55.335 0.070 55.405 ;
    END
  END rd_out[59]
  PIN rd_out[60]
    DIRECTION OUTPUT ;
    USE SIGNAL ;
    SHAPE ABUTMENT ;
    PORT
      LAYER metal3 ;
      RECT 0.000 55.615 0.070 55.685 ;
    END
  END rd_out[60]
  PIN rd_out[61]
    DIRECTION OUTPUT ;
    USE SIGNAL ;
    SHAPE ABUTMENT ;
    PORT
      LAYER metal3 ;
      RECT 0.000 55.895 0.070 55.965 ;
    END
  END rd_out[61]
  PIN rd_out[62]
    DIRECTION OUTPUT ;
    USE SIGNAL ;
    SHAPE ABUTMENT ;
    PORT
      LAYER metal3 ;
      RECT 0.000 56.175 0.070 56.245 ;
    END
  END rd_out[62]
  PIN rd_out[63]
    DIRECTION OUTPUT ;
    USE SIGNAL ;
    SHAPE ABUTMENT ;
    PORT
      LAYER metal3 ;
      RECT 0.000 56.455 0.070 56.525 ;
    END
  END rd_out[63]
  PIN rd_out[64]
    DIRECTION OUTPUT ;
    USE SIGNAL ;
    SHAPE ABUTMENT ;
    PORT
      LAYER metal3 ;
      RECT 0.000 56.735 0.070 56.805 ;
    END
  END rd_out[64]
  PIN rd_out[65]
    DIRECTION OUTPUT ;
    USE SIGNAL ;
    SHAPE ABUTMENT ;
    PORT
      LAYER metal3 ;
      RECT 0.000 57.015 0.070 57.085 ;
    END
  END rd_out[65]
  PIN rd_out[66]
    DIRECTION OUTPUT ;
    USE SIGNAL ;
    SHAPE ABUTMENT ;
    PORT
      LAYER metal3 ;
      RECT 0.000 57.295 0.070 57.365 ;
    END
  END rd_out[66]
  PIN rd_out[67]
    DIRECTION OUTPUT ;
    USE SIGNAL ;
    SHAPE ABUTMENT ;
    PORT
      LAYER metal3 ;
      RECT 0.000 57.575 0.070 57.645 ;
    END
  END rd_out[67]
  PIN rd_out[68]
    DIRECTION OUTPUT ;
    USE SIGNAL ;
    SHAPE ABUTMENT ;
    PORT
      LAYER metal3 ;
      RECT 0.000 57.855 0.070 57.925 ;
    END
  END rd_out[68]
  PIN rd_out[69]
    DIRECTION OUTPUT ;
    USE SIGNAL ;
    SHAPE ABUTMENT ;
    PORT
      LAYER metal3 ;
      RECT 0.000 58.135 0.070 58.205 ;
    END
  END rd_out[69]
  PIN rd_out[70]
    DIRECTION OUTPUT ;
    USE SIGNAL ;
    SHAPE ABUTMENT ;
    PORT
      LAYER metal3 ;
      RECT 0.000 58.415 0.070 58.485 ;
    END
  END rd_out[70]
  PIN rd_out[71]
    DIRECTION OUTPUT ;
    USE SIGNAL ;
    SHAPE ABUTMENT ;
    PORT
      LAYER metal3 ;
      RECT 0.000 58.695 0.070 58.765 ;
    END
  END rd_out[71]
  PIN rd_out[72]
    DIRECTION OUTPUT ;
    USE SIGNAL ;
    SHAPE ABUTMENT ;
    PORT
      LAYER metal3 ;
      RECT 0.000 58.975 0.070 59.045 ;
    END
  END rd_out[72]
  PIN rd_out[73]
    DIRECTION OUTPUT ;
    USE SIGNAL ;
    SHAPE ABUTMENT ;
    PORT
      LAYER metal3 ;
      RECT 0.000 59.255 0.070 59.325 ;
    END
  END rd_out[73]
  PIN rd_out[74]
    DIRECTION OUTPUT ;
    USE SIGNAL ;
    SHAPE ABUTMENT ;
    PORT
      LAYER metal3 ;
      RECT 0.000 59.535 0.070 59.605 ;
    END
  END rd_out[74]
  PIN rd_out[75]
    DIRECTION OUTPUT ;
    USE SIGNAL ;
    SHAPE ABUTMENT ;
    PORT
      LAYER metal3 ;
      RECT 0.000 59.815 0.070 59.885 ;
    END
  END rd_out[75]
  PIN rd_out[76]
    DIRECTION OUTPUT ;
    USE SIGNAL ;
    SHAPE ABUTMENT ;
    PORT
      LAYER metal3 ;
      RECT 0.000 60.095 0.070 60.165 ;
    END
  END rd_out[76]
  PIN rd_out[77]
    DIRECTION OUTPUT ;
    USE SIGNAL ;
    SHAPE ABUTMENT ;
    PORT
      LAYER metal3 ;
      RECT 0.000 60.375 0.070 60.445 ;
    END
  END rd_out[77]
  PIN rd_out[78]
    DIRECTION OUTPUT ;
    USE SIGNAL ;
    SHAPE ABUTMENT ;
    PORT
      LAYER metal3 ;
      RECT 0.000 60.655 0.070 60.725 ;
    END
  END rd_out[78]
  PIN rd_out[79]
    DIRECTION OUTPUT ;
    USE SIGNAL ;
    SHAPE ABUTMENT ;
    PORT
      LAYER metal3 ;
      RECT 0.000 60.935 0.070 61.005 ;
    END
  END rd_out[79]
  PIN rd_out[80]
    DIRECTION OUTPUT ;
    USE SIGNAL ;
    SHAPE ABUTMENT ;
    PORT
      LAYER metal3 ;
      RECT 0.000 61.215 0.070 61.285 ;
    END
  END rd_out[80]
  PIN rd_out[81]
    DIRECTION OUTPUT ;
    USE SIGNAL ;
    SHAPE ABUTMENT ;
    PORT
      LAYER metal3 ;
      RECT 0.000 61.495 0.070 61.565 ;
    END
  END rd_out[81]
  PIN rd_out[82]
    DIRECTION OUTPUT ;
    USE SIGNAL ;
    SHAPE ABUTMENT ;
    PORT
      LAYER metal3 ;
      RECT 0.000 61.775 0.070 61.845 ;
    END
  END rd_out[82]
  PIN rd_out[83]
    DIRECTION OUTPUT ;
    USE SIGNAL ;
    SHAPE ABUTMENT ;
    PORT
      LAYER metal3 ;
      RECT 0.000 62.055 0.070 62.125 ;
    END
  END rd_out[83]
  PIN rd_out[84]
    DIRECTION OUTPUT ;
    USE SIGNAL ;
    SHAPE ABUTMENT ;
    PORT
      LAYER metal3 ;
      RECT 0.000 62.335 0.070 62.405 ;
    END
  END rd_out[84]
  PIN rd_out[85]
    DIRECTION OUTPUT ;
    USE SIGNAL ;
    SHAPE ABUTMENT ;
    PORT
      LAYER metal3 ;
      RECT 0.000 62.615 0.070 62.685 ;
    END
  END rd_out[85]
  PIN rd_out[86]
    DIRECTION OUTPUT ;
    USE SIGNAL ;
    SHAPE ABUTMENT ;
    PORT
      LAYER metal3 ;
      RECT 0.000 62.895 0.070 62.965 ;
    END
  END rd_out[86]
  PIN rd_out[87]
    DIRECTION OUTPUT ;
    USE SIGNAL ;
    SHAPE ABUTMENT ;
    PORT
      LAYER metal3 ;
      RECT 0.000 63.175 0.070 63.245 ;
    END
  END rd_out[87]
  PIN rd_out[88]
    DIRECTION OUTPUT ;
    USE SIGNAL ;
    SHAPE ABUTMENT ;
    PORT
      LAYER metal3 ;
      RECT 0.000 63.455 0.070 63.525 ;
    END
  END rd_out[88]
  PIN rd_out[89]
    DIRECTION OUTPUT ;
    USE SIGNAL ;
    SHAPE ABUTMENT ;
    PORT
      LAYER metal3 ;
      RECT 0.000 63.735 0.070 63.805 ;
    END
  END rd_out[89]
  PIN rd_out[90]
    DIRECTION OUTPUT ;
    USE SIGNAL ;
    SHAPE ABUTMENT ;
    PORT
      LAYER metal3 ;
      RECT 0.000 64.015 0.070 64.085 ;
    END
  END rd_out[90]
  PIN rd_out[91]
    DIRECTION OUTPUT ;
    USE SIGNAL ;
    SHAPE ABUTMENT ;
    PORT
      LAYER metal3 ;
      RECT 0.000 64.295 0.070 64.365 ;
    END
  END rd_out[91]
  PIN rd_out[92]
    DIRECTION OUTPUT ;
    USE SIGNAL ;
    SHAPE ABUTMENT ;
    PORT
      LAYER metal3 ;
      RECT 0.000 64.575 0.070 64.645 ;
    END
  END rd_out[92]
  PIN rd_out[93]
    DIRECTION OUTPUT ;
    USE SIGNAL ;
    SHAPE ABUTMENT ;
    PORT
      LAYER metal3 ;
      RECT 0.000 64.855 0.070 64.925 ;
    END
  END rd_out[93]
  PIN rd_out[94]
    DIRECTION OUTPUT ;
    USE SIGNAL ;
    SHAPE ABUTMENT ;
    PORT
      LAYER metal3 ;
      RECT 0.000 65.135 0.070 65.205 ;
    END
  END rd_out[94]
  PIN rd_out[95]
    DIRECTION OUTPUT ;
    USE SIGNAL ;
    SHAPE ABUTMENT ;
    PORT
      LAYER metal3 ;
      RECT 0.000 65.415 0.070 65.485 ;
    END
  END rd_out[95]
  PIN rd_out[96]
    DIRECTION OUTPUT ;
    USE SIGNAL ;
    SHAPE ABUTMENT ;
    PORT
      LAYER metal3 ;
      RECT 0.000 65.695 0.070 65.765 ;
    END
  END rd_out[96]
  PIN rd_out[97]
    DIRECTION OUTPUT ;
    USE SIGNAL ;
    SHAPE ABUTMENT ;
    PORT
      LAYER metal3 ;
      RECT 0.000 65.975 0.070 66.045 ;
    END
  END rd_out[97]
  PIN rd_out[98]
    DIRECTION OUTPUT ;
    USE SIGNAL ;
    SHAPE ABUTMENT ;
    PORT
      LAYER metal3 ;
      RECT 0.000 66.255 0.070 66.325 ;
    END
  END rd_out[98]
  PIN rd_out[99]
    DIRECTION OUTPUT ;
    USE SIGNAL ;
    SHAPE ABUTMENT ;
    PORT
      LAYER metal3 ;
      RECT 0.000 66.535 0.070 66.605 ;
    END
  END rd_out[99]
  PIN rd_out[100]
    DIRECTION OUTPUT ;
    USE SIGNAL ;
    SHAPE ABUTMENT ;
    PORT
      LAYER metal3 ;
      RECT 0.000 66.815 0.070 66.885 ;
    END
  END rd_out[100]
  PIN rd_out[101]
    DIRECTION OUTPUT ;
    USE SIGNAL ;
    SHAPE ABUTMENT ;
    PORT
      LAYER metal3 ;
      RECT 0.000 67.095 0.070 67.165 ;
    END
  END rd_out[101]
  PIN rd_out[102]
    DIRECTION OUTPUT ;
    USE SIGNAL ;
    SHAPE ABUTMENT ;
    PORT
      LAYER metal3 ;
      RECT 0.000 67.375 0.070 67.445 ;
    END
  END rd_out[102]
  PIN rd_out[103]
    DIRECTION OUTPUT ;
    USE SIGNAL ;
    SHAPE ABUTMENT ;
    PORT
      LAYER metal3 ;
      RECT 0.000 67.655 0.070 67.725 ;
    END
  END rd_out[103]
  PIN rd_out[104]
    DIRECTION OUTPUT ;
    USE SIGNAL ;
    SHAPE ABUTMENT ;
    PORT
      LAYER metal3 ;
      RECT 0.000 67.935 0.070 68.005 ;
    END
  END rd_out[104]
  PIN rd_out[105]
    DIRECTION OUTPUT ;
    USE SIGNAL ;
    SHAPE ABUTMENT ;
    PORT
      LAYER metal3 ;
      RECT 0.000 68.215 0.070 68.285 ;
    END
  END rd_out[105]
  PIN rd_out[106]
    DIRECTION OUTPUT ;
    USE SIGNAL ;
    SHAPE ABUTMENT ;
    PORT
      LAYER metal3 ;
      RECT 0.000 68.495 0.070 68.565 ;
    END
  END rd_out[106]
  PIN rd_out[107]
    DIRECTION OUTPUT ;
    USE SIGNAL ;
    SHAPE ABUTMENT ;
    PORT
      LAYER metal3 ;
      RECT 0.000 68.775 0.070 68.845 ;
    END
  END rd_out[107]
  PIN rd_out[108]
    DIRECTION OUTPUT ;
    USE SIGNAL ;
    SHAPE ABUTMENT ;
    PORT
      LAYER metal3 ;
      RECT 0.000 69.055 0.070 69.125 ;
    END
  END rd_out[108]
  PIN rd_out[109]
    DIRECTION OUTPUT ;
    USE SIGNAL ;
    SHAPE ABUTMENT ;
    PORT
      LAYER metal3 ;
      RECT 0.000 69.335 0.070 69.405 ;
    END
  END rd_out[109]
  PIN rd_out[110]
    DIRECTION OUTPUT ;
    USE SIGNAL ;
    SHAPE ABUTMENT ;
    PORT
      LAYER metal3 ;
      RECT 0.000 69.615 0.070 69.685 ;
    END
  END rd_out[110]
  PIN rd_out[111]
    DIRECTION OUTPUT ;
    USE SIGNAL ;
    SHAPE ABUTMENT ;
    PORT
      LAYER metal3 ;
      RECT 0.000 69.895 0.070 69.965 ;
    END
  END rd_out[111]
  PIN rd_out[112]
    DIRECTION OUTPUT ;
    USE SIGNAL ;
    SHAPE ABUTMENT ;
    PORT
      LAYER metal3 ;
      RECT 0.000 70.175 0.070 70.245 ;
    END
  END rd_out[112]
  PIN rd_out[113]
    DIRECTION OUTPUT ;
    USE SIGNAL ;
    SHAPE ABUTMENT ;
    PORT
      LAYER metal3 ;
      RECT 0.000 70.455 0.070 70.525 ;
    END
  END rd_out[113]
  PIN rd_out[114]
    DIRECTION OUTPUT ;
    USE SIGNAL ;
    SHAPE ABUTMENT ;
    PORT
      LAYER metal3 ;
      RECT 0.000 70.735 0.070 70.805 ;
    END
  END rd_out[114]
  PIN rd_out[115]
    DIRECTION OUTPUT ;
    USE SIGNAL ;
    SHAPE ABUTMENT ;
    PORT
      LAYER metal3 ;
      RECT 0.000 71.015 0.070 71.085 ;
    END
  END rd_out[115]
  PIN rd_out[116]
    DIRECTION OUTPUT ;
    USE SIGNAL ;
    SHAPE ABUTMENT ;
    PORT
      LAYER metal3 ;
      RECT 0.000 71.295 0.070 71.365 ;
    END
  END rd_out[116]
  PIN rd_out[117]
    DIRECTION OUTPUT ;
    USE SIGNAL ;
    SHAPE ABUTMENT ;
    PORT
      LAYER metal3 ;
      RECT 0.000 71.575 0.070 71.645 ;
    END
  END rd_out[117]
  PIN rd_out[118]
    DIRECTION OUTPUT ;
    USE SIGNAL ;
    SHAPE ABUTMENT ;
    PORT
      LAYER metal3 ;
      RECT 0.000 71.855 0.070 71.925 ;
    END
  END rd_out[118]
  PIN rd_out[119]
    DIRECTION OUTPUT ;
    USE SIGNAL ;
    SHAPE ABUTMENT ;
    PORT
      LAYER metal3 ;
      RECT 0.000 72.135 0.070 72.205 ;
    END
  END rd_out[119]
  PIN rd_out[120]
    DIRECTION OUTPUT ;
    USE SIGNAL ;
    SHAPE ABUTMENT ;
    PORT
      LAYER metal3 ;
      RECT 0.000 72.415 0.070 72.485 ;
    END
  END rd_out[120]
  PIN rd_out[121]
    DIRECTION OUTPUT ;
    USE SIGNAL ;
    SHAPE ABUTMENT ;
    PORT
      LAYER metal3 ;
      RECT 0.000 72.695 0.070 72.765 ;
    END
  END rd_out[121]
  PIN rd_out[122]
    DIRECTION OUTPUT ;
    USE SIGNAL ;
    SHAPE ABUTMENT ;
    PORT
      LAYER metal3 ;
      RECT 0.000 72.975 0.070 73.045 ;
    END
  END rd_out[122]
  PIN rd_out[123]
    DIRECTION OUTPUT ;
    USE SIGNAL ;
    SHAPE ABUTMENT ;
    PORT
      LAYER metal3 ;
      RECT 0.000 73.255 0.070 73.325 ;
    END
  END rd_out[123]
  PIN rd_out[124]
    DIRECTION OUTPUT ;
    USE SIGNAL ;
    SHAPE ABUTMENT ;
    PORT
      LAYER metal3 ;
      RECT 0.000 73.535 0.070 73.605 ;
    END
  END rd_out[124]
  PIN rd_out[125]
    DIRECTION OUTPUT ;
    USE SIGNAL ;
    SHAPE ABUTMENT ;
    PORT
      LAYER metal3 ;
      RECT 0.000 73.815 0.070 73.885 ;
    END
  END rd_out[125]
  PIN rd_out[126]
    DIRECTION OUTPUT ;
    USE SIGNAL ;
    SHAPE ABUTMENT ;
    PORT
      LAYER metal3 ;
      RECT 0.000 74.095 0.070 74.165 ;
    END
  END rd_out[126]
  PIN rd_out[127]
    DIRECTION OUTPUT ;
    USE SIGNAL ;
    SHAPE ABUTMENT ;
    PORT
      LAYER metal3 ;
      RECT 0.000 74.375 0.070 74.445 ;
    END
  END rd_out[127]
  PIN wd_in[0]
    DIRECTION INPUT ;
    USE SIGNAL ;
    SHAPE ABUTMENT ;
    PORT
      LAYER metal3 ;
      RECT 0.000 75.495 0.070 75.565 ;
    END
  END wd_in[0]
  PIN wd_in[1]
    DIRECTION INPUT ;
    USE SIGNAL ;
    SHAPE ABUTMENT ;
    PORT
      LAYER metal3 ;
      RECT 0.000 75.775 0.070 75.845 ;
    END
  END wd_in[1]
  PIN wd_in[2]
    DIRECTION INPUT ;
    USE SIGNAL ;
    SHAPE ABUTMENT ;
    PORT
      LAYER metal3 ;
      RECT 0.000 76.055 0.070 76.125 ;
    END
  END wd_in[2]
  PIN wd_in[3]
    DIRECTION INPUT ;
    USE SIGNAL ;
    SHAPE ABUTMENT ;
    PORT
      LAYER metal3 ;
      RECT 0.000 76.335 0.070 76.405 ;
    END
  END wd_in[3]
  PIN wd_in[4]
    DIRECTION INPUT ;
    USE SIGNAL ;
    SHAPE ABUTMENT ;
    PORT
      LAYER metal3 ;
      RECT 0.000 76.615 0.070 76.685 ;
    END
  END wd_in[4]
  PIN wd_in[5]
    DIRECTION INPUT ;
    USE SIGNAL ;
    SHAPE ABUTMENT ;
    PORT
      LAYER metal3 ;
      RECT 0.000 76.895 0.070 76.965 ;
    END
  END wd_in[5]
  PIN wd_in[6]
    DIRECTION INPUT ;
    USE SIGNAL ;
    SHAPE ABUTMENT ;
    PORT
      LAYER metal3 ;
      RECT 0.000 77.175 0.070 77.245 ;
    END
  END wd_in[6]
  PIN wd_in[7]
    DIRECTION INPUT ;
    USE SIGNAL ;
    SHAPE ABUTMENT ;
    PORT
      LAYER metal3 ;
      RECT 0.000 77.455 0.070 77.525 ;
    END
  END wd_in[7]
  PIN wd_in[8]
    DIRECTION INPUT ;
    USE SIGNAL ;
    SHAPE ABUTMENT ;
    PORT
      LAYER metal3 ;
      RECT 0.000 77.735 0.070 77.805 ;
    END
  END wd_in[8]
  PIN wd_in[9]
    DIRECTION INPUT ;
    USE SIGNAL ;
    SHAPE ABUTMENT ;
    PORT
      LAYER metal3 ;
      RECT 0.000 78.015 0.070 78.085 ;
    END
  END wd_in[9]
  PIN wd_in[10]
    DIRECTION INPUT ;
    USE SIGNAL ;
    SHAPE ABUTMENT ;
    PORT
      LAYER metal3 ;
      RECT 0.000 78.295 0.070 78.365 ;
    END
  END wd_in[10]
  PIN wd_in[11]
    DIRECTION INPUT ;
    USE SIGNAL ;
    SHAPE ABUTMENT ;
    PORT
      LAYER metal3 ;
      RECT 0.000 78.575 0.070 78.645 ;
    END
  END wd_in[11]
  PIN wd_in[12]
    DIRECTION INPUT ;
    USE SIGNAL ;
    SHAPE ABUTMENT ;
    PORT
      LAYER metal3 ;
      RECT 0.000 78.855 0.070 78.925 ;
    END
  END wd_in[12]
  PIN wd_in[13]
    DIRECTION INPUT ;
    USE SIGNAL ;
    SHAPE ABUTMENT ;
    PORT
      LAYER metal3 ;
      RECT 0.000 79.135 0.070 79.205 ;
    END
  END wd_in[13]
  PIN wd_in[14]
    DIRECTION INPUT ;
    USE SIGNAL ;
    SHAPE ABUTMENT ;
    PORT
      LAYER metal3 ;
      RECT 0.000 79.415 0.070 79.485 ;
    END
  END wd_in[14]
  PIN wd_in[15]
    DIRECTION INPUT ;
    USE SIGNAL ;
    SHAPE ABUTMENT ;
    PORT
      LAYER metal3 ;
      RECT 0.000 79.695 0.070 79.765 ;
    END
  END wd_in[15]
  PIN wd_in[16]
    DIRECTION INPUT ;
    USE SIGNAL ;
    SHAPE ABUTMENT ;
    PORT
      LAYER metal3 ;
      RECT 0.000 79.975 0.070 80.045 ;
    END
  END wd_in[16]
  PIN wd_in[17]
    DIRECTION INPUT ;
    USE SIGNAL ;
    SHAPE ABUTMENT ;
    PORT
      LAYER metal3 ;
      RECT 0.000 80.255 0.070 80.325 ;
    END
  END wd_in[17]
  PIN wd_in[18]
    DIRECTION INPUT ;
    USE SIGNAL ;
    SHAPE ABUTMENT ;
    PORT
      LAYER metal3 ;
      RECT 0.000 80.535 0.070 80.605 ;
    END
  END wd_in[18]
  PIN wd_in[19]
    DIRECTION INPUT ;
    USE SIGNAL ;
    SHAPE ABUTMENT ;
    PORT
      LAYER metal3 ;
      RECT 0.000 80.815 0.070 80.885 ;
    END
  END wd_in[19]
  PIN wd_in[20]
    DIRECTION INPUT ;
    USE SIGNAL ;
    SHAPE ABUTMENT ;
    PORT
      LAYER metal3 ;
      RECT 0.000 81.095 0.070 81.165 ;
    END
  END wd_in[20]
  PIN wd_in[21]
    DIRECTION INPUT ;
    USE SIGNAL ;
    SHAPE ABUTMENT ;
    PORT
      LAYER metal3 ;
      RECT 0.000 81.375 0.070 81.445 ;
    END
  END wd_in[21]
  PIN wd_in[22]
    DIRECTION INPUT ;
    USE SIGNAL ;
    SHAPE ABUTMENT ;
    PORT
      LAYER metal3 ;
      RECT 0.000 81.655 0.070 81.725 ;
    END
  END wd_in[22]
  PIN wd_in[23]
    DIRECTION INPUT ;
    USE SIGNAL ;
    SHAPE ABUTMENT ;
    PORT
      LAYER metal3 ;
      RECT 0.000 81.935 0.070 82.005 ;
    END
  END wd_in[23]
  PIN wd_in[24]
    DIRECTION INPUT ;
    USE SIGNAL ;
    SHAPE ABUTMENT ;
    PORT
      LAYER metal3 ;
      RECT 0.000 82.215 0.070 82.285 ;
    END
  END wd_in[24]
  PIN wd_in[25]
    DIRECTION INPUT ;
    USE SIGNAL ;
    SHAPE ABUTMENT ;
    PORT
      LAYER metal3 ;
      RECT 0.000 82.495 0.070 82.565 ;
    END
  END wd_in[25]
  PIN wd_in[26]
    DIRECTION INPUT ;
    USE SIGNAL ;
    SHAPE ABUTMENT ;
    PORT
      LAYER metal3 ;
      RECT 0.000 82.775 0.070 82.845 ;
    END
  END wd_in[26]
  PIN wd_in[27]
    DIRECTION INPUT ;
    USE SIGNAL ;
    SHAPE ABUTMENT ;
    PORT
      LAYER metal3 ;
      RECT 0.000 83.055 0.070 83.125 ;
    END
  END wd_in[27]
  PIN wd_in[28]
    DIRECTION INPUT ;
    USE SIGNAL ;
    SHAPE ABUTMENT ;
    PORT
      LAYER metal3 ;
      RECT 0.000 83.335 0.070 83.405 ;
    END
  END wd_in[28]
  PIN wd_in[29]
    DIRECTION INPUT ;
    USE SIGNAL ;
    SHAPE ABUTMENT ;
    PORT
      LAYER metal3 ;
      RECT 0.000 83.615 0.070 83.685 ;
    END
  END wd_in[29]
  PIN wd_in[30]
    DIRECTION INPUT ;
    USE SIGNAL ;
    SHAPE ABUTMENT ;
    PORT
      LAYER metal3 ;
      RECT 0.000 83.895 0.070 83.965 ;
    END
  END wd_in[30]
  PIN wd_in[31]
    DIRECTION INPUT ;
    USE SIGNAL ;
    SHAPE ABUTMENT ;
    PORT
      LAYER metal3 ;
      RECT 0.000 84.175 0.070 84.245 ;
    END
  END wd_in[31]
  PIN wd_in[32]
    DIRECTION INPUT ;
    USE SIGNAL ;
    SHAPE ABUTMENT ;
    PORT
      LAYER metal3 ;
      RECT 0.000 84.455 0.070 84.525 ;
    END
  END wd_in[32]
  PIN wd_in[33]
    DIRECTION INPUT ;
    USE SIGNAL ;
    SHAPE ABUTMENT ;
    PORT
      LAYER metal3 ;
      RECT 0.000 84.735 0.070 84.805 ;
    END
  END wd_in[33]
  PIN wd_in[34]
    DIRECTION INPUT ;
    USE SIGNAL ;
    SHAPE ABUTMENT ;
    PORT
      LAYER metal3 ;
      RECT 0.000 85.015 0.070 85.085 ;
    END
  END wd_in[34]
  PIN wd_in[35]
    DIRECTION INPUT ;
    USE SIGNAL ;
    SHAPE ABUTMENT ;
    PORT
      LAYER metal3 ;
      RECT 0.000 85.295 0.070 85.365 ;
    END
  END wd_in[35]
  PIN wd_in[36]
    DIRECTION INPUT ;
    USE SIGNAL ;
    SHAPE ABUTMENT ;
    PORT
      LAYER metal3 ;
      RECT 0.000 85.575 0.070 85.645 ;
    END
  END wd_in[36]
  PIN wd_in[37]
    DIRECTION INPUT ;
    USE SIGNAL ;
    SHAPE ABUTMENT ;
    PORT
      LAYER metal3 ;
      RECT 0.000 85.855 0.070 85.925 ;
    END
  END wd_in[37]
  PIN wd_in[38]
    DIRECTION INPUT ;
    USE SIGNAL ;
    SHAPE ABUTMENT ;
    PORT
      LAYER metal3 ;
      RECT 0.000 86.135 0.070 86.205 ;
    END
  END wd_in[38]
  PIN wd_in[39]
    DIRECTION INPUT ;
    USE SIGNAL ;
    SHAPE ABUTMENT ;
    PORT
      LAYER metal3 ;
      RECT 0.000 86.415 0.070 86.485 ;
    END
  END wd_in[39]
  PIN wd_in[40]
    DIRECTION INPUT ;
    USE SIGNAL ;
    SHAPE ABUTMENT ;
    PORT
      LAYER metal3 ;
      RECT 0.000 86.695 0.070 86.765 ;
    END
  END wd_in[40]
  PIN wd_in[41]
    DIRECTION INPUT ;
    USE SIGNAL ;
    SHAPE ABUTMENT ;
    PORT
      LAYER metal3 ;
      RECT 0.000 86.975 0.070 87.045 ;
    END
  END wd_in[41]
  PIN wd_in[42]
    DIRECTION INPUT ;
    USE SIGNAL ;
    SHAPE ABUTMENT ;
    PORT
      LAYER metal3 ;
      RECT 0.000 87.255 0.070 87.325 ;
    END
  END wd_in[42]
  PIN wd_in[43]
    DIRECTION INPUT ;
    USE SIGNAL ;
    SHAPE ABUTMENT ;
    PORT
      LAYER metal3 ;
      RECT 0.000 87.535 0.070 87.605 ;
    END
  END wd_in[43]
  PIN wd_in[44]
    DIRECTION INPUT ;
    USE SIGNAL ;
    SHAPE ABUTMENT ;
    PORT
      LAYER metal3 ;
      RECT 0.000 87.815 0.070 87.885 ;
    END
  END wd_in[44]
  PIN wd_in[45]
    DIRECTION INPUT ;
    USE SIGNAL ;
    SHAPE ABUTMENT ;
    PORT
      LAYER metal3 ;
      RECT 0.000 88.095 0.070 88.165 ;
    END
  END wd_in[45]
  PIN wd_in[46]
    DIRECTION INPUT ;
    USE SIGNAL ;
    SHAPE ABUTMENT ;
    PORT
      LAYER metal3 ;
      RECT 0.000 88.375 0.070 88.445 ;
    END
  END wd_in[46]
  PIN wd_in[47]
    DIRECTION INPUT ;
    USE SIGNAL ;
    SHAPE ABUTMENT ;
    PORT
      LAYER metal3 ;
      RECT 0.000 88.655 0.070 88.725 ;
    END
  END wd_in[47]
  PIN wd_in[48]
    DIRECTION INPUT ;
    USE SIGNAL ;
    SHAPE ABUTMENT ;
    PORT
      LAYER metal3 ;
      RECT 0.000 88.935 0.070 89.005 ;
    END
  END wd_in[48]
  PIN wd_in[49]
    DIRECTION INPUT ;
    USE SIGNAL ;
    SHAPE ABUTMENT ;
    PORT
      LAYER metal3 ;
      RECT 0.000 89.215 0.070 89.285 ;
    END
  END wd_in[49]
  PIN wd_in[50]
    DIRECTION INPUT ;
    USE SIGNAL ;
    SHAPE ABUTMENT ;
    PORT
      LAYER metal3 ;
      RECT 0.000 89.495 0.070 89.565 ;
    END
  END wd_in[50]
  PIN wd_in[51]
    DIRECTION INPUT ;
    USE SIGNAL ;
    SHAPE ABUTMENT ;
    PORT
      LAYER metal3 ;
      RECT 0.000 89.775 0.070 89.845 ;
    END
  END wd_in[51]
  PIN wd_in[52]
    DIRECTION INPUT ;
    USE SIGNAL ;
    SHAPE ABUTMENT ;
    PORT
      LAYER metal3 ;
      RECT 0.000 90.055 0.070 90.125 ;
    END
  END wd_in[52]
  PIN wd_in[53]
    DIRECTION INPUT ;
    USE SIGNAL ;
    SHAPE ABUTMENT ;
    PORT
      LAYER metal3 ;
      RECT 0.000 90.335 0.070 90.405 ;
    END
  END wd_in[53]
  PIN wd_in[54]
    DIRECTION INPUT ;
    USE SIGNAL ;
    SHAPE ABUTMENT ;
    PORT
      LAYER metal3 ;
      RECT 0.000 90.615 0.070 90.685 ;
    END
  END wd_in[54]
  PIN wd_in[55]
    DIRECTION INPUT ;
    USE SIGNAL ;
    SHAPE ABUTMENT ;
    PORT
      LAYER metal3 ;
      RECT 0.000 90.895 0.070 90.965 ;
    END
  END wd_in[55]
  PIN wd_in[56]
    DIRECTION INPUT ;
    USE SIGNAL ;
    SHAPE ABUTMENT ;
    PORT
      LAYER metal3 ;
      RECT 0.000 91.175 0.070 91.245 ;
    END
  END wd_in[56]
  PIN wd_in[57]
    DIRECTION INPUT ;
    USE SIGNAL ;
    SHAPE ABUTMENT ;
    PORT
      LAYER metal3 ;
      RECT 0.000 91.455 0.070 91.525 ;
    END
  END wd_in[57]
  PIN wd_in[58]
    DIRECTION INPUT ;
    USE SIGNAL ;
    SHAPE ABUTMENT ;
    PORT
      LAYER metal3 ;
      RECT 0.000 91.735 0.070 91.805 ;
    END
  END wd_in[58]
  PIN wd_in[59]
    DIRECTION INPUT ;
    USE SIGNAL ;
    SHAPE ABUTMENT ;
    PORT
      LAYER metal3 ;
      RECT 0.000 92.015 0.070 92.085 ;
    END
  END wd_in[59]
  PIN wd_in[60]
    DIRECTION INPUT ;
    USE SIGNAL ;
    SHAPE ABUTMENT ;
    PORT
      LAYER metal3 ;
      RECT 0.000 92.295 0.070 92.365 ;
    END
  END wd_in[60]
  PIN wd_in[61]
    DIRECTION INPUT ;
    USE SIGNAL ;
    SHAPE ABUTMENT ;
    PORT
      LAYER metal3 ;
      RECT 0.000 92.575 0.070 92.645 ;
    END
  END wd_in[61]
  PIN wd_in[62]
    DIRECTION INPUT ;
    USE SIGNAL ;
    SHAPE ABUTMENT ;
    PORT
      LAYER metal3 ;
      RECT 0.000 92.855 0.070 92.925 ;
    END
  END wd_in[62]
  PIN wd_in[63]
    DIRECTION INPUT ;
    USE SIGNAL ;
    SHAPE ABUTMENT ;
    PORT
      LAYER metal3 ;
      RECT 0.000 93.135 0.070 93.205 ;
    END
  END wd_in[63]
  PIN wd_in[64]
    DIRECTION INPUT ;
    USE SIGNAL ;
    SHAPE ABUTMENT ;
    PORT
      LAYER metal3 ;
      RECT 0.000 93.415 0.070 93.485 ;
    END
  END wd_in[64]
  PIN wd_in[65]
    DIRECTION INPUT ;
    USE SIGNAL ;
    SHAPE ABUTMENT ;
    PORT
      LAYER metal3 ;
      RECT 0.000 93.695 0.070 93.765 ;
    END
  END wd_in[65]
  PIN wd_in[66]
    DIRECTION INPUT ;
    USE SIGNAL ;
    SHAPE ABUTMENT ;
    PORT
      LAYER metal3 ;
      RECT 0.000 93.975 0.070 94.045 ;
    END
  END wd_in[66]
  PIN wd_in[67]
    DIRECTION INPUT ;
    USE SIGNAL ;
    SHAPE ABUTMENT ;
    PORT
      LAYER metal3 ;
      RECT 0.000 94.255 0.070 94.325 ;
    END
  END wd_in[67]
  PIN wd_in[68]
    DIRECTION INPUT ;
    USE SIGNAL ;
    SHAPE ABUTMENT ;
    PORT
      LAYER metal3 ;
      RECT 0.000 94.535 0.070 94.605 ;
    END
  END wd_in[68]
  PIN wd_in[69]
    DIRECTION INPUT ;
    USE SIGNAL ;
    SHAPE ABUTMENT ;
    PORT
      LAYER metal3 ;
      RECT 0.000 94.815 0.070 94.885 ;
    END
  END wd_in[69]
  PIN wd_in[70]
    DIRECTION INPUT ;
    USE SIGNAL ;
    SHAPE ABUTMENT ;
    PORT
      LAYER metal3 ;
      RECT 0.000 95.095 0.070 95.165 ;
    END
  END wd_in[70]
  PIN wd_in[71]
    DIRECTION INPUT ;
    USE SIGNAL ;
    SHAPE ABUTMENT ;
    PORT
      LAYER metal3 ;
      RECT 0.000 95.375 0.070 95.445 ;
    END
  END wd_in[71]
  PIN wd_in[72]
    DIRECTION INPUT ;
    USE SIGNAL ;
    SHAPE ABUTMENT ;
    PORT
      LAYER metal3 ;
      RECT 0.000 95.655 0.070 95.725 ;
    END
  END wd_in[72]
  PIN wd_in[73]
    DIRECTION INPUT ;
    USE SIGNAL ;
    SHAPE ABUTMENT ;
    PORT
      LAYER metal3 ;
      RECT 0.000 95.935 0.070 96.005 ;
    END
  END wd_in[73]
  PIN wd_in[74]
    DIRECTION INPUT ;
    USE SIGNAL ;
    SHAPE ABUTMENT ;
    PORT
      LAYER metal3 ;
      RECT 0.000 96.215 0.070 96.285 ;
    END
  END wd_in[74]
  PIN wd_in[75]
    DIRECTION INPUT ;
    USE SIGNAL ;
    SHAPE ABUTMENT ;
    PORT
      LAYER metal3 ;
      RECT 0.000 96.495 0.070 96.565 ;
    END
  END wd_in[75]
  PIN wd_in[76]
    DIRECTION INPUT ;
    USE SIGNAL ;
    SHAPE ABUTMENT ;
    PORT
      LAYER metal3 ;
      RECT 0.000 96.775 0.070 96.845 ;
    END
  END wd_in[76]
  PIN wd_in[77]
    DIRECTION INPUT ;
    USE SIGNAL ;
    SHAPE ABUTMENT ;
    PORT
      LAYER metal3 ;
      RECT 0.000 97.055 0.070 97.125 ;
    END
  END wd_in[77]
  PIN wd_in[78]
    DIRECTION INPUT ;
    USE SIGNAL ;
    SHAPE ABUTMENT ;
    PORT
      LAYER metal3 ;
      RECT 0.000 97.335 0.070 97.405 ;
    END
  END wd_in[78]
  PIN wd_in[79]
    DIRECTION INPUT ;
    USE SIGNAL ;
    SHAPE ABUTMENT ;
    PORT
      LAYER metal3 ;
      RECT 0.000 97.615 0.070 97.685 ;
    END
  END wd_in[79]
  PIN wd_in[80]
    DIRECTION INPUT ;
    USE SIGNAL ;
    SHAPE ABUTMENT ;
    PORT
      LAYER metal3 ;
      RECT 0.000 97.895 0.070 97.965 ;
    END
  END wd_in[80]
  PIN wd_in[81]
    DIRECTION INPUT ;
    USE SIGNAL ;
    SHAPE ABUTMENT ;
    PORT
      LAYER metal3 ;
      RECT 0.000 98.175 0.070 98.245 ;
    END
  END wd_in[81]
  PIN wd_in[82]
    DIRECTION INPUT ;
    USE SIGNAL ;
    SHAPE ABUTMENT ;
    PORT
      LAYER metal3 ;
      RECT 0.000 98.455 0.070 98.525 ;
    END
  END wd_in[82]
  PIN wd_in[83]
    DIRECTION INPUT ;
    USE SIGNAL ;
    SHAPE ABUTMENT ;
    PORT
      LAYER metal3 ;
      RECT 0.000 98.735 0.070 98.805 ;
    END
  END wd_in[83]
  PIN wd_in[84]
    DIRECTION INPUT ;
    USE SIGNAL ;
    SHAPE ABUTMENT ;
    PORT
      LAYER metal3 ;
      RECT 0.000 99.015 0.070 99.085 ;
    END
  END wd_in[84]
  PIN wd_in[85]
    DIRECTION INPUT ;
    USE SIGNAL ;
    SHAPE ABUTMENT ;
    PORT
      LAYER metal3 ;
      RECT 0.000 99.295 0.070 99.365 ;
    END
  END wd_in[85]
  PIN wd_in[86]
    DIRECTION INPUT ;
    USE SIGNAL ;
    SHAPE ABUTMENT ;
    PORT
      LAYER metal3 ;
      RECT 0.000 99.575 0.070 99.645 ;
    END
  END wd_in[86]
  PIN wd_in[87]
    DIRECTION INPUT ;
    USE SIGNAL ;
    SHAPE ABUTMENT ;
    PORT
      LAYER metal3 ;
      RECT 0.000 99.855 0.070 99.925 ;
    END
  END wd_in[87]
  PIN wd_in[88]
    DIRECTION INPUT ;
    USE SIGNAL ;
    SHAPE ABUTMENT ;
    PORT
      LAYER metal3 ;
      RECT 0.000 100.135 0.070 100.205 ;
    END
  END wd_in[88]
  PIN wd_in[89]
    DIRECTION INPUT ;
    USE SIGNAL ;
    SHAPE ABUTMENT ;
    PORT
      LAYER metal3 ;
      RECT 0.000 100.415 0.070 100.485 ;
    END
  END wd_in[89]
  PIN wd_in[90]
    DIRECTION INPUT ;
    USE SIGNAL ;
    SHAPE ABUTMENT ;
    PORT
      LAYER metal3 ;
      RECT 0.000 100.695 0.070 100.765 ;
    END
  END wd_in[90]
  PIN wd_in[91]
    DIRECTION INPUT ;
    USE SIGNAL ;
    SHAPE ABUTMENT ;
    PORT
      LAYER metal3 ;
      RECT 0.000 100.975 0.070 101.045 ;
    END
  END wd_in[91]
  PIN wd_in[92]
    DIRECTION INPUT ;
    USE SIGNAL ;
    SHAPE ABUTMENT ;
    PORT
      LAYER metal3 ;
      RECT 0.000 101.255 0.070 101.325 ;
    END
  END wd_in[92]
  PIN wd_in[93]
    DIRECTION INPUT ;
    USE SIGNAL ;
    SHAPE ABUTMENT ;
    PORT
      LAYER metal3 ;
      RECT 0.000 101.535 0.070 101.605 ;
    END
  END wd_in[93]
  PIN wd_in[94]
    DIRECTION INPUT ;
    USE SIGNAL ;
    SHAPE ABUTMENT ;
    PORT
      LAYER metal3 ;
      RECT 0.000 101.815 0.070 101.885 ;
    END
  END wd_in[94]
  PIN wd_in[95]
    DIRECTION INPUT ;
    USE SIGNAL ;
    SHAPE ABUTMENT ;
    PORT
      LAYER metal3 ;
      RECT 0.000 102.095 0.070 102.165 ;
    END
  END wd_in[95]
  PIN wd_in[96]
    DIRECTION INPUT ;
    USE SIGNAL ;
    SHAPE ABUTMENT ;
    PORT
      LAYER metal3 ;
      RECT 0.000 102.375 0.070 102.445 ;
    END
  END wd_in[96]
  PIN wd_in[97]
    DIRECTION INPUT ;
    USE SIGNAL ;
    SHAPE ABUTMENT ;
    PORT
      LAYER metal3 ;
      RECT 0.000 102.655 0.070 102.725 ;
    END
  END wd_in[97]
  PIN wd_in[98]
    DIRECTION INPUT ;
    USE SIGNAL ;
    SHAPE ABUTMENT ;
    PORT
      LAYER metal3 ;
      RECT 0.000 102.935 0.070 103.005 ;
    END
  END wd_in[98]
  PIN wd_in[99]
    DIRECTION INPUT ;
    USE SIGNAL ;
    SHAPE ABUTMENT ;
    PORT
      LAYER metal3 ;
      RECT 0.000 103.215 0.070 103.285 ;
    END
  END wd_in[99]
  PIN wd_in[100]
    DIRECTION INPUT ;
    USE SIGNAL ;
    SHAPE ABUTMENT ;
    PORT
      LAYER metal3 ;
      RECT 0.000 103.495 0.070 103.565 ;
    END
  END wd_in[100]
  PIN wd_in[101]
    DIRECTION INPUT ;
    USE SIGNAL ;
    SHAPE ABUTMENT ;
    PORT
      LAYER metal3 ;
      RECT 0.000 103.775 0.070 103.845 ;
    END
  END wd_in[101]
  PIN wd_in[102]
    DIRECTION INPUT ;
    USE SIGNAL ;
    SHAPE ABUTMENT ;
    PORT
      LAYER metal3 ;
      RECT 0.000 104.055 0.070 104.125 ;
    END
  END wd_in[102]
  PIN wd_in[103]
    DIRECTION INPUT ;
    USE SIGNAL ;
    SHAPE ABUTMENT ;
    PORT
      LAYER metal3 ;
      RECT 0.000 104.335 0.070 104.405 ;
    END
  END wd_in[103]
  PIN wd_in[104]
    DIRECTION INPUT ;
    USE SIGNAL ;
    SHAPE ABUTMENT ;
    PORT
      LAYER metal3 ;
      RECT 0.000 104.615 0.070 104.685 ;
    END
  END wd_in[104]
  PIN wd_in[105]
    DIRECTION INPUT ;
    USE SIGNAL ;
    SHAPE ABUTMENT ;
    PORT
      LAYER metal3 ;
      RECT 0.000 104.895 0.070 104.965 ;
    END
  END wd_in[105]
  PIN wd_in[106]
    DIRECTION INPUT ;
    USE SIGNAL ;
    SHAPE ABUTMENT ;
    PORT
      LAYER metal3 ;
      RECT 0.000 105.175 0.070 105.245 ;
    END
  END wd_in[106]
  PIN wd_in[107]
    DIRECTION INPUT ;
    USE SIGNAL ;
    SHAPE ABUTMENT ;
    PORT
      LAYER metal3 ;
      RECT 0.000 105.455 0.070 105.525 ;
    END
  END wd_in[107]
  PIN wd_in[108]
    DIRECTION INPUT ;
    USE SIGNAL ;
    SHAPE ABUTMENT ;
    PORT
      LAYER metal3 ;
      RECT 0.000 105.735 0.070 105.805 ;
    END
  END wd_in[108]
  PIN wd_in[109]
    DIRECTION INPUT ;
    USE SIGNAL ;
    SHAPE ABUTMENT ;
    PORT
      LAYER metal3 ;
      RECT 0.000 106.015 0.070 106.085 ;
    END
  END wd_in[109]
  PIN wd_in[110]
    DIRECTION INPUT ;
    USE SIGNAL ;
    SHAPE ABUTMENT ;
    PORT
      LAYER metal3 ;
      RECT 0.000 106.295 0.070 106.365 ;
    END
  END wd_in[110]
  PIN wd_in[111]
    DIRECTION INPUT ;
    USE SIGNAL ;
    SHAPE ABUTMENT ;
    PORT
      LAYER metal3 ;
      RECT 0.000 106.575 0.070 106.645 ;
    END
  END wd_in[111]
  PIN wd_in[112]
    DIRECTION INPUT ;
    USE SIGNAL ;
    SHAPE ABUTMENT ;
    PORT
      LAYER metal3 ;
      RECT 0.000 106.855 0.070 106.925 ;
    END
  END wd_in[112]
  PIN wd_in[113]
    DIRECTION INPUT ;
    USE SIGNAL ;
    SHAPE ABUTMENT ;
    PORT
      LAYER metal3 ;
      RECT 0.000 107.135 0.070 107.205 ;
    END
  END wd_in[113]
  PIN wd_in[114]
    DIRECTION INPUT ;
    USE SIGNAL ;
    SHAPE ABUTMENT ;
    PORT
      LAYER metal3 ;
      RECT 0.000 107.415 0.070 107.485 ;
    END
  END wd_in[114]
  PIN wd_in[115]
    DIRECTION INPUT ;
    USE SIGNAL ;
    SHAPE ABUTMENT ;
    PORT
      LAYER metal3 ;
      RECT 0.000 107.695 0.070 107.765 ;
    END
  END wd_in[115]
  PIN wd_in[116]
    DIRECTION INPUT ;
    USE SIGNAL ;
    SHAPE ABUTMENT ;
    PORT
      LAYER metal3 ;
      RECT 0.000 107.975 0.070 108.045 ;
    END
  END wd_in[116]
  PIN wd_in[117]
    DIRECTION INPUT ;
    USE SIGNAL ;
    SHAPE ABUTMENT ;
    PORT
      LAYER metal3 ;
      RECT 0.000 108.255 0.070 108.325 ;
    END
  END wd_in[117]
  PIN wd_in[118]
    DIRECTION INPUT ;
    USE SIGNAL ;
    SHAPE ABUTMENT ;
    PORT
      LAYER metal3 ;
      RECT 0.000 108.535 0.070 108.605 ;
    END
  END wd_in[118]
  PIN wd_in[119]
    DIRECTION INPUT ;
    USE SIGNAL ;
    SHAPE ABUTMENT ;
    PORT
      LAYER metal3 ;
      RECT 0.000 108.815 0.070 108.885 ;
    END
  END wd_in[119]
  PIN wd_in[120]
    DIRECTION INPUT ;
    USE SIGNAL ;
    SHAPE ABUTMENT ;
    PORT
      LAYER metal3 ;
      RECT 0.000 109.095 0.070 109.165 ;
    END
  END wd_in[120]
  PIN wd_in[121]
    DIRECTION INPUT ;
    USE SIGNAL ;
    SHAPE ABUTMENT ;
    PORT
      LAYER metal3 ;
      RECT 0.000 109.375 0.070 109.445 ;
    END
  END wd_in[121]
  PIN wd_in[122]
    DIRECTION INPUT ;
    USE SIGNAL ;
    SHAPE ABUTMENT ;
    PORT
      LAYER metal3 ;
      RECT 0.000 109.655 0.070 109.725 ;
    END
  END wd_in[122]
  PIN wd_in[123]
    DIRECTION INPUT ;
    USE SIGNAL ;
    SHAPE ABUTMENT ;
    PORT
      LAYER metal3 ;
      RECT 0.000 109.935 0.070 110.005 ;
    END
  END wd_in[123]
  PIN wd_in[124]
    DIRECTION INPUT ;
    USE SIGNAL ;
    SHAPE ABUTMENT ;
    PORT
      LAYER metal3 ;
      RECT 0.000 110.215 0.070 110.285 ;
    END
  END wd_in[124]
  PIN wd_in[125]
    DIRECTION INPUT ;
    USE SIGNAL ;
    SHAPE ABUTMENT ;
    PORT
      LAYER metal3 ;
      RECT 0.000 110.495 0.070 110.565 ;
    END
  END wd_in[125]
  PIN wd_in[126]
    DIRECTION INPUT ;
    USE SIGNAL ;
    SHAPE ABUTMENT ;
    PORT
      LAYER metal3 ;
      RECT 0.000 110.775 0.070 110.845 ;
    END
  END wd_in[126]
  PIN wd_in[127]
    DIRECTION INPUT ;
    USE SIGNAL ;
    SHAPE ABUTMENT ;
    PORT
      LAYER metal3 ;
      RECT 0.000 111.055 0.070 111.125 ;
    END
  END wd_in[127]
  PIN addr_in[0]
    DIRECTION INPUT ;
    USE SIGNAL ;
    SHAPE ABUTMENT ;
    PORT
      LAYER metal3 ;
      RECT 0.000 112.175 0.070 112.245 ;
    END
  END addr_in[0]
  PIN addr_in[1]
    DIRECTION INPUT ;
    USE SIGNAL ;
    SHAPE ABUTMENT ;
    PORT
      LAYER metal3 ;
      RECT 0.000 112.455 0.070 112.525 ;
    END
  END addr_in[1]
  PIN addr_in[2]
    DIRECTION INPUT ;
    USE SIGNAL ;
    SHAPE ABUTMENT ;
    PORT
      LAYER metal3 ;
      RECT 0.000 112.735 0.070 112.805 ;
    END
  END addr_in[2]
  PIN addr_in[3]
    DIRECTION INPUT ;
    USE SIGNAL ;
    SHAPE ABUTMENT ;
    PORT
      LAYER metal3 ;
      RECT 0.000 113.015 0.070 113.085 ;
    END
  END addr_in[3]
  PIN addr_in[4]
    DIRECTION INPUT ;
    USE SIGNAL ;
    SHAPE ABUTMENT ;
    PORT
      LAYER metal3 ;
      RECT 0.000 113.295 0.070 113.365 ;
    END
  END addr_in[4]
  PIN addr_in[5]
    DIRECTION INPUT ;
    USE SIGNAL ;
    SHAPE ABUTMENT ;
    PORT
      LAYER metal3 ;
      RECT 0.000 113.575 0.070 113.645 ;
    END
  END addr_in[5]
  PIN addr_in[6]
    DIRECTION INPUT ;
    USE SIGNAL ;
    SHAPE ABUTMENT ;
    PORT
      LAYER metal3 ;
      RECT 0.000 113.855 0.070 113.925 ;
    END
  END addr_in[6]
  PIN addr_in[7]
    DIRECTION INPUT ;
    USE SIGNAL ;
    SHAPE ABUTMENT ;
    PORT
      LAYER metal3 ;
      RECT 0.000 114.135 0.070 114.205 ;
    END
  END addr_in[7]
  PIN addr_in[8]
    DIRECTION INPUT ;
    USE SIGNAL ;
    SHAPE ABUTMENT ;
    PORT
      LAYER metal3 ;
      RECT 0.000 114.415 0.070 114.485 ;
    END
  END addr_in[8]
  PIN addr_in[9]
    DIRECTION INPUT ;
    USE SIGNAL ;
    SHAPE ABUTMENT ;
    PORT
      LAYER metal3 ;
      RECT 0.000 114.695 0.070 114.765 ;
    END
  END addr_in[9]
  PIN addr_in[10]
    DIRECTION INPUT ;
    USE SIGNAL ;
    SHAPE ABUTMENT ;
    PORT
      LAYER metal3 ;
      RECT 0.000 114.975 0.070 115.045 ;
    END
  END addr_in[10]
  PIN addr_in[11]
    DIRECTION INPUT ;
    USE SIGNAL ;
    SHAPE ABUTMENT ;
    PORT
      LAYER metal3 ;
      RECT 0.000 115.255 0.070 115.325 ;
    END
  END addr_in[11]
  PIN addr_in[12]
    DIRECTION INPUT ;
    USE SIGNAL ;
    SHAPE ABUTMENT ;
    PORT
      LAYER metal3 ;
      RECT 0.000 115.535 0.070 115.605 ;
    END
  END addr_in[12]
  PIN we_in
    DIRECTION INPUT ;
    USE SIGNAL ;
    SHAPE ABUTMENT ;
    PORT
      LAYER metal3 ;
      RECT 0.000 115.815 0.070 115.885 ;
    END
  END we_in
  PIN ce_in
    DIRECTION INPUT ;
    USE SIGNAL ;
    SHAPE ABUTMENT ;
    PORT
      LAYER metal3 ;
      RECT 0.000 116.095 0.070 116.165 ;
    END
  END ce_in
  PIN clk
    DIRECTION INPUT ;
    USE SIGNAL ;
    SHAPE ABUTMENT ;
    PORT
      LAYER metal3 ;
      RECT 0.000 116.375 0.070 116.445 ;
    END
  END clk
  PIN VSS
    DIRECTION INOUT ;
    USE GROUND ;
    PORT
      LAYER metal4 ;
      RECT 1.960 2.100 2.240 758.100 ;
      RECT 5.320 2.100 5.600 758.100 ;
      RECT 8.680 2.100 8.960 758.100 ;
      RECT 12.040 2.100 12.320 758.100 ;
      RECT 15.400 2.100 15.680 758.100 ;
      RECT 18.760 2.100 19.040 758.100 ;
      RECT 22.120 2.100 22.400 758.100 ;
      RECT 25.480 2.100 25.760 758.100 ;
      RECT 28.840 2.100 29.120 758.100 ;
      RECT 32.200 2.100 32.480 758.100 ;
      RECT 35.560 2.100 35.840 758.100 ;
      RECT 38.920 2.100 39.200 758.100 ;
      RECT 42.280 2.100 42.560 758.100 ;
      RECT 45.640 2.100 45.920 758.100 ;
      RECT 49.000 2.100 49.280 758.100 ;
      RECT 52.360 2.100 52.640 758.100 ;
      RECT 55.720 2.100 56.000 758.100 ;
      RECT 59.080 2.100 59.360 758.100 ;
      RECT 62.440 2.100 62.720 758.100 ;
      RECT 65.800 2.100 66.080 758.100 ;
      RECT 69.160 2.100 69.440 758.100 ;
      RECT 72.520 2.100 72.800 758.100 ;
      RECT 75.880 2.100 76.160 758.100 ;
      RECT 79.240 2.100 79.520 758.100 ;
      RECT 82.600 2.100 82.880 758.100 ;
      RECT 85.960 2.100 86.240 758.100 ;
      RECT 89.320 2.100 89.600 758.100 ;
      RECT 92.680 2.100 92.960 758.100 ;
      RECT 96.040 2.100 96.320 758.100 ;
      RECT 99.400 2.100 99.680 758.100 ;
      RECT 102.760 2.100 103.040 758.100 ;
      RECT 106.120 2.100 106.400 758.100 ;
      RECT 109.480 2.100 109.760 758.100 ;
      RECT 112.840 2.100 113.120 758.100 ;
      RECT 116.200 2.100 116.480 758.100 ;
      RECT 119.560 2.100 119.840 758.100 ;
      RECT 122.920 2.100 123.200 758.100 ;
      RECT 126.280 2.100 126.560 758.100 ;
      RECT 129.640 2.100 129.920 758.100 ;
      RECT 133.000 2.100 133.280 758.100 ;
      RECT 136.360 2.100 136.640 758.100 ;
      RECT 139.720 2.100 140.000 758.100 ;
      RECT 143.080 2.100 143.360 758.100 ;
      RECT 146.440 2.100 146.720 758.100 ;
      RECT 149.800 2.100 150.080 758.100 ;
      RECT 153.160 2.100 153.440 758.100 ;
      RECT 156.520 2.100 156.800 758.100 ;
      RECT 159.880 2.100 160.160 758.100 ;
      RECT 163.240 2.100 163.520 758.100 ;
      RECT 166.600 2.100 166.880 758.100 ;
      RECT 169.960 2.100 170.240 758.100 ;
      RECT 173.320 2.100 173.600 758.100 ;
      RECT 176.680 2.100 176.960 758.100 ;
      RECT 180.040 2.100 180.320 758.100 ;
      RECT 183.400 2.100 183.680 758.100 ;
      RECT 186.760 2.100 187.040 758.100 ;
      RECT 190.120 2.100 190.400 758.100 ;
      RECT 193.480 2.100 193.760 758.100 ;
      RECT 196.840 2.100 197.120 758.100 ;
      RECT 200.200 2.100 200.480 758.100 ;
      RECT 203.560 2.100 203.840 758.100 ;
      RECT 206.920 2.100 207.200 758.100 ;
      RECT 210.280 2.100 210.560 758.100 ;
      RECT 213.640 2.100 213.920 758.100 ;
      RECT 217.000 2.100 217.280 758.100 ;
      RECT 220.360 2.100 220.640 758.100 ;
      RECT 223.720 2.100 224.000 758.100 ;
      RECT 227.080 2.100 227.360 758.100 ;
      RECT 230.440 2.100 230.720 758.100 ;
      RECT 233.800 2.100 234.080 758.100 ;
      RECT 237.160 2.100 237.440 758.100 ;
      RECT 240.520 2.100 240.800 758.100 ;
      RECT 243.880 2.100 244.160 758.100 ;
      RECT 247.240 2.100 247.520 758.100 ;
      RECT 250.600 2.100 250.880 758.100 ;
      RECT 253.960 2.100 254.240 758.100 ;
      RECT 257.320 2.100 257.600 758.100 ;
      RECT 260.680 2.100 260.960 758.100 ;
      RECT 264.040 2.100 264.320 758.100 ;
      RECT 267.400 2.100 267.680 758.100 ;
      RECT 270.760 2.100 271.040 758.100 ;
      RECT 274.120 2.100 274.400 758.100 ;
      RECT 277.480 2.100 277.760 758.100 ;
      RECT 280.840 2.100 281.120 758.100 ;
      RECT 284.200 2.100 284.480 758.100 ;
      RECT 287.560 2.100 287.840 758.100 ;
      RECT 290.920 2.100 291.200 758.100 ;
      RECT 294.280 2.100 294.560 758.100 ;
      RECT 297.640 2.100 297.920 758.100 ;
      RECT 301.000 2.100 301.280 758.100 ;
      RECT 304.360 2.100 304.640 758.100 ;
      RECT 307.720 2.100 308.000 758.100 ;
      RECT 311.080 2.100 311.360 758.100 ;
      RECT 314.440 2.100 314.720 758.100 ;
      RECT 317.800 2.100 318.080 758.100 ;
      RECT 321.160 2.100 321.440 758.100 ;
      RECT 324.520 2.100 324.800 758.100 ;
      RECT 327.880 2.100 328.160 758.100 ;
      RECT 331.240 2.100 331.520 758.100 ;
      RECT 334.600 2.100 334.880 758.100 ;
      RECT 337.960 2.100 338.240 758.100 ;
      RECT 341.320 2.100 341.600 758.100 ;
      RECT 344.680 2.100 344.960 758.100 ;
      RECT 348.040 2.100 348.320 758.100 ;
      RECT 351.400 2.100 351.680 758.100 ;
      RECT 354.760 2.100 355.040 758.100 ;
      RECT 358.120 2.100 358.400 758.100 ;
      RECT 361.480 2.100 361.760 758.100 ;
      RECT 364.840 2.100 365.120 758.100 ;
      RECT 368.200 2.100 368.480 758.100 ;
      RECT 371.560 2.100 371.840 758.100 ;
      RECT 374.920 2.100 375.200 758.100 ;
      RECT 378.280 2.100 378.560 758.100 ;
      RECT 381.640 2.100 381.920 758.100 ;
      RECT 385.000 2.100 385.280 758.100 ;
      RECT 388.360 2.100 388.640 758.100 ;
      RECT 391.720 2.100 392.000 758.100 ;
      RECT 395.080 2.100 395.360 758.100 ;
      RECT 398.440 2.100 398.720 758.100 ;
      RECT 401.800 2.100 402.080 758.100 ;
      RECT 405.160 2.100 405.440 758.100 ;
      RECT 408.520 2.100 408.800 758.100 ;
      RECT 411.880 2.100 412.160 758.100 ;
      RECT 415.240 2.100 415.520 758.100 ;
      RECT 418.600 2.100 418.880 758.100 ;
      RECT 421.960 2.100 422.240 758.100 ;
      RECT 425.320 2.100 425.600 758.100 ;
      RECT 428.680 2.100 428.960 758.100 ;
      RECT 432.040 2.100 432.320 758.100 ;
      RECT 435.400 2.100 435.680 758.100 ;
      RECT 438.760 2.100 439.040 758.100 ;
      RECT 442.120 2.100 442.400 758.100 ;
      RECT 445.480 2.100 445.760 758.100 ;
      RECT 448.840 2.100 449.120 758.100 ;
      RECT 452.200 2.100 452.480 758.100 ;
      RECT 455.560 2.100 455.840 758.100 ;
      RECT 458.920 2.100 459.200 758.100 ;
      RECT 462.280 2.100 462.560 758.100 ;
      RECT 465.640 2.100 465.920 758.100 ;
      RECT 469.000 2.100 469.280 758.100 ;
      RECT 472.360 2.100 472.640 758.100 ;
      RECT 475.720 2.100 476.000 758.100 ;
      RECT 479.080 2.100 479.360 758.100 ;
      RECT 482.440 2.100 482.720 758.100 ;
      RECT 485.800 2.100 486.080 758.100 ;
      RECT 489.160 2.100 489.440 758.100 ;
      RECT 492.520 2.100 492.800 758.100 ;
      RECT 495.880 2.100 496.160 758.100 ;
      RECT 499.240 2.100 499.520 758.100 ;
      RECT 502.600 2.100 502.880 758.100 ;
      RECT 505.960 2.100 506.240 758.100 ;
      RECT 509.320 2.100 509.600 758.100 ;
      RECT 512.680 2.100 512.960 758.100 ;
      RECT 516.040 2.100 516.320 758.100 ;
      RECT 519.400 2.100 519.680 758.100 ;
      RECT 522.760 2.100 523.040 758.100 ;
      RECT 526.120 2.100 526.400 758.100 ;
      RECT 529.480 2.100 529.760 758.100 ;
      RECT 532.840 2.100 533.120 758.100 ;
      RECT 536.200 2.100 536.480 758.100 ;
      RECT 539.560 2.100 539.840 758.100 ;
      RECT 542.920 2.100 543.200 758.100 ;
      RECT 546.280 2.100 546.560 758.100 ;
      RECT 549.640 2.100 549.920 758.100 ;
      RECT 553.000 2.100 553.280 758.100 ;
      RECT 556.360 2.100 556.640 758.100 ;
      RECT 559.720 2.100 560.000 758.100 ;
      RECT 563.080 2.100 563.360 758.100 ;
      RECT 566.440 2.100 566.720 758.100 ;
      RECT 569.800 2.100 570.080 758.100 ;
      RECT 573.160 2.100 573.440 758.100 ;
      RECT 576.520 2.100 576.800 758.100 ;
      RECT 579.880 2.100 580.160 758.100 ;
      RECT 583.240 2.100 583.520 758.100 ;
      RECT 586.600 2.100 586.880 758.100 ;
      RECT 589.960 2.100 590.240 758.100 ;
      RECT 593.320 2.100 593.600 758.100 ;
      RECT 596.680 2.100 596.960 758.100 ;
      RECT 600.040 2.100 600.320 758.100 ;
      RECT 603.400 2.100 603.680 758.100 ;
      RECT 606.760 2.100 607.040 758.100 ;
      RECT 610.120 2.100 610.400 758.100 ;
      RECT 613.480 2.100 613.760 758.100 ;
      RECT 616.840 2.100 617.120 758.100 ;
      RECT 620.200 2.100 620.480 758.100 ;
      RECT 623.560 2.100 623.840 758.100 ;
      RECT 626.920 2.100 627.200 758.100 ;
      RECT 630.280 2.100 630.560 758.100 ;
      RECT 633.640 2.100 633.920 758.100 ;
      RECT 637.000 2.100 637.280 758.100 ;
      RECT 640.360 2.100 640.640 758.100 ;
      RECT 643.720 2.100 644.000 758.100 ;
      RECT 647.080 2.100 647.360 758.100 ;
      RECT 650.440 2.100 650.720 758.100 ;
      RECT 653.800 2.100 654.080 758.100 ;
      RECT 657.160 2.100 657.440 758.100 ;
      RECT 660.520 2.100 660.800 758.100 ;
      RECT 663.880 2.100 664.160 758.100 ;
      RECT 667.240 2.100 667.520 758.100 ;
      RECT 670.600 2.100 670.880 758.100 ;
      RECT 673.960 2.100 674.240 758.100 ;
      RECT 677.320 2.100 677.600 758.100 ;
      RECT 680.680 2.100 680.960 758.100 ;
      RECT 684.040 2.100 684.320 758.100 ;
      RECT 687.400 2.100 687.680 758.100 ;
      RECT 690.760 2.100 691.040 758.100 ;
      RECT 694.120 2.100 694.400 758.100 ;
      RECT 697.480 2.100 697.760 758.100 ;
      RECT 700.840 2.100 701.120 758.100 ;
      RECT 704.200 2.100 704.480 758.100 ;
      RECT 707.560 2.100 707.840 758.100 ;
      RECT 710.920 2.100 711.200 758.100 ;
      RECT 714.280 2.100 714.560 758.100 ;
      RECT 717.640 2.100 717.920 758.100 ;
      RECT 721.000 2.100 721.280 758.100 ;
      RECT 724.360 2.100 724.640 758.100 ;
      RECT 727.720 2.100 728.000 758.100 ;
      RECT 731.080 2.100 731.360 758.100 ;
      RECT 734.440 2.100 734.720 758.100 ;
      RECT 737.800 2.100 738.080 758.100 ;
      RECT 741.160 2.100 741.440 758.100 ;
      RECT 744.520 2.100 744.800 758.100 ;
      RECT 747.880 2.100 748.160 758.100 ;
      RECT 751.240 2.100 751.520 758.100 ;
      RECT 754.600 2.100 754.880 758.100 ;
    END
  END VSS
  PIN VDD
    DIRECTION INOUT ;
    USE POWER ;
    PORT
      LAYER metal4 ;
      RECT 3.640 2.100 3.920 758.100 ;
      RECT 7.000 2.100 7.280 758.100 ;
      RECT 10.360 2.100 10.640 758.100 ;
      RECT 13.720 2.100 14.000 758.100 ;
      RECT 17.080 2.100 17.360 758.100 ;
      RECT 20.440 2.100 20.720 758.100 ;
      RECT 23.800 2.100 24.080 758.100 ;
      RECT 27.160 2.100 27.440 758.100 ;
      RECT 30.520 2.100 30.800 758.100 ;
      RECT 33.880 2.100 34.160 758.100 ;
      RECT 37.240 2.100 37.520 758.100 ;
      RECT 40.600 2.100 40.880 758.100 ;
      RECT 43.960 2.100 44.240 758.100 ;
      RECT 47.320 2.100 47.600 758.100 ;
      RECT 50.680 2.100 50.960 758.100 ;
      RECT 54.040 2.100 54.320 758.100 ;
      RECT 57.400 2.100 57.680 758.100 ;
      RECT 60.760 2.100 61.040 758.100 ;
      RECT 64.120 2.100 64.400 758.100 ;
      RECT 67.480 2.100 67.760 758.100 ;
      RECT 70.840 2.100 71.120 758.100 ;
      RECT 74.200 2.100 74.480 758.100 ;
      RECT 77.560 2.100 77.840 758.100 ;
      RECT 80.920 2.100 81.200 758.100 ;
      RECT 84.280 2.100 84.560 758.100 ;
      RECT 87.640 2.100 87.920 758.100 ;
      RECT 91.000 2.100 91.280 758.100 ;
      RECT 94.360 2.100 94.640 758.100 ;
      RECT 97.720 2.100 98.000 758.100 ;
      RECT 101.080 2.100 101.360 758.100 ;
      RECT 104.440 2.100 104.720 758.100 ;
      RECT 107.800 2.100 108.080 758.100 ;
      RECT 111.160 2.100 111.440 758.100 ;
      RECT 114.520 2.100 114.800 758.100 ;
      RECT 117.880 2.100 118.160 758.100 ;
      RECT 121.240 2.100 121.520 758.100 ;
      RECT 124.600 2.100 124.880 758.100 ;
      RECT 127.960 2.100 128.240 758.100 ;
      RECT 131.320 2.100 131.600 758.100 ;
      RECT 134.680 2.100 134.960 758.100 ;
      RECT 138.040 2.100 138.320 758.100 ;
      RECT 141.400 2.100 141.680 758.100 ;
      RECT 144.760 2.100 145.040 758.100 ;
      RECT 148.120 2.100 148.400 758.100 ;
      RECT 151.480 2.100 151.760 758.100 ;
      RECT 154.840 2.100 155.120 758.100 ;
      RECT 158.200 2.100 158.480 758.100 ;
      RECT 161.560 2.100 161.840 758.100 ;
      RECT 164.920 2.100 165.200 758.100 ;
      RECT 168.280 2.100 168.560 758.100 ;
      RECT 171.640 2.100 171.920 758.100 ;
      RECT 175.000 2.100 175.280 758.100 ;
      RECT 178.360 2.100 178.640 758.100 ;
      RECT 181.720 2.100 182.000 758.100 ;
      RECT 185.080 2.100 185.360 758.100 ;
      RECT 188.440 2.100 188.720 758.100 ;
      RECT 191.800 2.100 192.080 758.100 ;
      RECT 195.160 2.100 195.440 758.100 ;
      RECT 198.520 2.100 198.800 758.100 ;
      RECT 201.880 2.100 202.160 758.100 ;
      RECT 205.240 2.100 205.520 758.100 ;
      RECT 208.600 2.100 208.880 758.100 ;
      RECT 211.960 2.100 212.240 758.100 ;
      RECT 215.320 2.100 215.600 758.100 ;
      RECT 218.680 2.100 218.960 758.100 ;
      RECT 222.040 2.100 222.320 758.100 ;
      RECT 225.400 2.100 225.680 758.100 ;
      RECT 228.760 2.100 229.040 758.100 ;
      RECT 232.120 2.100 232.400 758.100 ;
      RECT 235.480 2.100 235.760 758.100 ;
      RECT 238.840 2.100 239.120 758.100 ;
      RECT 242.200 2.100 242.480 758.100 ;
      RECT 245.560 2.100 245.840 758.100 ;
      RECT 248.920 2.100 249.200 758.100 ;
      RECT 252.280 2.100 252.560 758.100 ;
      RECT 255.640 2.100 255.920 758.100 ;
      RECT 259.000 2.100 259.280 758.100 ;
      RECT 262.360 2.100 262.640 758.100 ;
      RECT 265.720 2.100 266.000 758.100 ;
      RECT 269.080 2.100 269.360 758.100 ;
      RECT 272.440 2.100 272.720 758.100 ;
      RECT 275.800 2.100 276.080 758.100 ;
      RECT 279.160 2.100 279.440 758.100 ;
      RECT 282.520 2.100 282.800 758.100 ;
      RECT 285.880 2.100 286.160 758.100 ;
      RECT 289.240 2.100 289.520 758.100 ;
      RECT 292.600 2.100 292.880 758.100 ;
      RECT 295.960 2.100 296.240 758.100 ;
      RECT 299.320 2.100 299.600 758.100 ;
      RECT 302.680 2.100 302.960 758.100 ;
      RECT 306.040 2.100 306.320 758.100 ;
      RECT 309.400 2.100 309.680 758.100 ;
      RECT 312.760 2.100 313.040 758.100 ;
      RECT 316.120 2.100 316.400 758.100 ;
      RECT 319.480 2.100 319.760 758.100 ;
      RECT 322.840 2.100 323.120 758.100 ;
      RECT 326.200 2.100 326.480 758.100 ;
      RECT 329.560 2.100 329.840 758.100 ;
      RECT 332.920 2.100 333.200 758.100 ;
      RECT 336.280 2.100 336.560 758.100 ;
      RECT 339.640 2.100 339.920 758.100 ;
      RECT 343.000 2.100 343.280 758.100 ;
      RECT 346.360 2.100 346.640 758.100 ;
      RECT 349.720 2.100 350.000 758.100 ;
      RECT 353.080 2.100 353.360 758.100 ;
      RECT 356.440 2.100 356.720 758.100 ;
      RECT 359.800 2.100 360.080 758.100 ;
      RECT 363.160 2.100 363.440 758.100 ;
      RECT 366.520 2.100 366.800 758.100 ;
      RECT 369.880 2.100 370.160 758.100 ;
      RECT 373.240 2.100 373.520 758.100 ;
      RECT 376.600 2.100 376.880 758.100 ;
      RECT 379.960 2.100 380.240 758.100 ;
      RECT 383.320 2.100 383.600 758.100 ;
      RECT 386.680 2.100 386.960 758.100 ;
      RECT 390.040 2.100 390.320 758.100 ;
      RECT 393.400 2.100 393.680 758.100 ;
      RECT 396.760 2.100 397.040 758.100 ;
      RECT 400.120 2.100 400.400 758.100 ;
      RECT 403.480 2.100 403.760 758.100 ;
      RECT 406.840 2.100 407.120 758.100 ;
      RECT 410.200 2.100 410.480 758.100 ;
      RECT 413.560 2.100 413.840 758.100 ;
      RECT 416.920 2.100 417.200 758.100 ;
      RECT 420.280 2.100 420.560 758.100 ;
      RECT 423.640 2.100 423.920 758.100 ;
      RECT 427.000 2.100 427.280 758.100 ;
      RECT 430.360 2.100 430.640 758.100 ;
      RECT 433.720 2.100 434.000 758.100 ;
      RECT 437.080 2.100 437.360 758.100 ;
      RECT 440.440 2.100 440.720 758.100 ;
      RECT 443.800 2.100 444.080 758.100 ;
      RECT 447.160 2.100 447.440 758.100 ;
      RECT 450.520 2.100 450.800 758.100 ;
      RECT 453.880 2.100 454.160 758.100 ;
      RECT 457.240 2.100 457.520 758.100 ;
      RECT 460.600 2.100 460.880 758.100 ;
      RECT 463.960 2.100 464.240 758.100 ;
      RECT 467.320 2.100 467.600 758.100 ;
      RECT 470.680 2.100 470.960 758.100 ;
      RECT 474.040 2.100 474.320 758.100 ;
      RECT 477.400 2.100 477.680 758.100 ;
      RECT 480.760 2.100 481.040 758.100 ;
      RECT 484.120 2.100 484.400 758.100 ;
      RECT 487.480 2.100 487.760 758.100 ;
      RECT 490.840 2.100 491.120 758.100 ;
      RECT 494.200 2.100 494.480 758.100 ;
      RECT 497.560 2.100 497.840 758.100 ;
      RECT 500.920 2.100 501.200 758.100 ;
      RECT 504.280 2.100 504.560 758.100 ;
      RECT 507.640 2.100 507.920 758.100 ;
      RECT 511.000 2.100 511.280 758.100 ;
      RECT 514.360 2.100 514.640 758.100 ;
      RECT 517.720 2.100 518.000 758.100 ;
      RECT 521.080 2.100 521.360 758.100 ;
      RECT 524.440 2.100 524.720 758.100 ;
      RECT 527.800 2.100 528.080 758.100 ;
      RECT 531.160 2.100 531.440 758.100 ;
      RECT 534.520 2.100 534.800 758.100 ;
      RECT 537.880 2.100 538.160 758.100 ;
      RECT 541.240 2.100 541.520 758.100 ;
      RECT 544.600 2.100 544.880 758.100 ;
      RECT 547.960 2.100 548.240 758.100 ;
      RECT 551.320 2.100 551.600 758.100 ;
      RECT 554.680 2.100 554.960 758.100 ;
      RECT 558.040 2.100 558.320 758.100 ;
      RECT 561.400 2.100 561.680 758.100 ;
      RECT 564.760 2.100 565.040 758.100 ;
      RECT 568.120 2.100 568.400 758.100 ;
      RECT 571.480 2.100 571.760 758.100 ;
      RECT 574.840 2.100 575.120 758.100 ;
      RECT 578.200 2.100 578.480 758.100 ;
      RECT 581.560 2.100 581.840 758.100 ;
      RECT 584.920 2.100 585.200 758.100 ;
      RECT 588.280 2.100 588.560 758.100 ;
      RECT 591.640 2.100 591.920 758.100 ;
      RECT 595.000 2.100 595.280 758.100 ;
      RECT 598.360 2.100 598.640 758.100 ;
      RECT 601.720 2.100 602.000 758.100 ;
      RECT 605.080 2.100 605.360 758.100 ;
      RECT 608.440 2.100 608.720 758.100 ;
      RECT 611.800 2.100 612.080 758.100 ;
      RECT 615.160 2.100 615.440 758.100 ;
      RECT 618.520 2.100 618.800 758.100 ;
      RECT 621.880 2.100 622.160 758.100 ;
      RECT 625.240 2.100 625.520 758.100 ;
      RECT 628.600 2.100 628.880 758.100 ;
      RECT 631.960 2.100 632.240 758.100 ;
      RECT 635.320 2.100 635.600 758.100 ;
      RECT 638.680 2.100 638.960 758.100 ;
      RECT 642.040 2.100 642.320 758.100 ;
      RECT 645.400 2.100 645.680 758.100 ;
      RECT 648.760 2.100 649.040 758.100 ;
      RECT 652.120 2.100 652.400 758.100 ;
      RECT 655.480 2.100 655.760 758.100 ;
      RECT 658.840 2.100 659.120 758.100 ;
      RECT 662.200 2.100 662.480 758.100 ;
      RECT 665.560 2.100 665.840 758.100 ;
      RECT 668.920 2.100 669.200 758.100 ;
      RECT 672.280 2.100 672.560 758.100 ;
      RECT 675.640 2.100 675.920 758.100 ;
      RECT 679.000 2.100 679.280 758.100 ;
      RECT 682.360 2.100 682.640 758.100 ;
      RECT 685.720 2.100 686.000 758.100 ;
      RECT 689.080 2.100 689.360 758.100 ;
      RECT 692.440 2.100 692.720 758.100 ;
      RECT 695.800 2.100 696.080 758.100 ;
      RECT 699.160 2.100 699.440 758.100 ;
      RECT 702.520 2.100 702.800 758.100 ;
      RECT 705.880 2.100 706.160 758.100 ;
      RECT 709.240 2.100 709.520 758.100 ;
      RECT 712.600 2.100 712.880 758.100 ;
      RECT 715.960 2.100 716.240 758.100 ;
      RECT 719.320 2.100 719.600 758.100 ;
      RECT 722.680 2.100 722.960 758.100 ;
      RECT 726.040 2.100 726.320 758.100 ;
      RECT 729.400 2.100 729.680 758.100 ;
      RECT 732.760 2.100 733.040 758.100 ;
      RECT 736.120 2.100 736.400 758.100 ;
      RECT 739.480 2.100 739.760 758.100 ;
      RECT 742.840 2.100 743.120 758.100 ;
      RECT 746.200 2.100 746.480 758.100 ;
      RECT 749.560 2.100 749.840 758.100 ;
      RECT 752.920 2.100 753.200 758.100 ;
      RECT 756.280 2.100 756.560 758.100 ;
    END
  END VDD
  OBS
    LAYER metal1 ;
    RECT 0 0 760.000 760.200 ;
    LAYER metal2 ;
    RECT 0 0 760.000 760.200 ;
    LAYER metal3 ;
    RECT 0.070 0 760.000 760.200 ;
    RECT 0 0.000 0.070 2.070 ;
    RECT 0 2.270 0.070 2.350 ;
    RECT 0 2.550 0.070 2.630 ;
    RECT 0 2.830 0.070 2.910 ;
    RECT 0 3.110 0.070 3.190 ;
    RECT 0 3.390 0.070 3.470 ;
    RECT 0 3.670 0.070 3.750 ;
    RECT 0 3.950 0.070 4.030 ;
    RECT 0 4.230 0.070 4.310 ;
    RECT 0 4.510 0.070 4.590 ;
    RECT 0 4.790 0.070 4.870 ;
    RECT 0 5.070 0.070 5.150 ;
    RECT 0 5.350 0.070 5.430 ;
    RECT 0 5.630 0.070 5.710 ;
    RECT 0 5.910 0.070 5.990 ;
    RECT 0 6.190 0.070 6.270 ;
    RECT 0 6.470 0.070 6.550 ;
    RECT 0 6.750 0.070 6.830 ;
    RECT 0 7.030 0.070 7.110 ;
    RECT 0 7.310 0.070 7.390 ;
    RECT 0 7.590 0.070 7.670 ;
    RECT 0 7.870 0.070 7.950 ;
    RECT 0 8.150 0.070 8.230 ;
    RECT 0 8.430 0.070 8.510 ;
    RECT 0 8.710 0.070 8.790 ;
    RECT 0 8.990 0.070 9.070 ;
    RECT 0 9.270 0.070 9.350 ;
    RECT 0 9.550 0.070 9.630 ;
    RECT 0 9.830 0.070 9.910 ;
    RECT 0 10.110 0.070 10.190 ;
    RECT 0 10.390 0.070 10.470 ;
    RECT 0 10.670 0.070 10.750 ;
    RECT 0 10.950 0.070 11.030 ;
    RECT 0 11.230 0.070 11.310 ;
    RECT 0 11.510 0.070 11.590 ;
    RECT 0 11.790 0.070 11.870 ;
    RECT 0 12.070 0.070 12.150 ;
    RECT 0 12.350 0.070 12.430 ;
    RECT 0 12.630 0.070 12.710 ;
    RECT 0 12.910 0.070 12.990 ;
    RECT 0 13.190 0.070 13.270 ;
    RECT 0 13.470 0.070 13.550 ;
    RECT 0 13.750 0.070 13.830 ;
    RECT 0 14.030 0.070 14.110 ;
    RECT 0 14.310 0.070 14.390 ;
    RECT 0 14.590 0.070 14.670 ;
    RECT 0 14.870 0.070 14.950 ;
    RECT 0 15.150 0.070 15.230 ;
    RECT 0 15.430 0.070 15.510 ;
    RECT 0 15.710 0.070 15.790 ;
    RECT 0 15.990 0.070 16.070 ;
    RECT 0 16.270 0.070 16.350 ;
    RECT 0 16.550 0.070 16.630 ;
    RECT 0 16.830 0.070 16.910 ;
    RECT 0 17.110 0.070 17.190 ;
    RECT 0 17.390 0.070 17.470 ;
    RECT 0 17.670 0.070 17.750 ;
    RECT 0 17.950 0.070 18.030 ;
    RECT 0 18.230 0.070 18.310 ;
    RECT 0 18.510 0.070 18.590 ;
    RECT 0 18.790 0.070 18.870 ;
    RECT 0 19.070 0.070 19.150 ;
    RECT 0 19.350 0.070 19.430 ;
    RECT 0 19.630 0.070 19.710 ;
    RECT 0 19.910 0.070 19.990 ;
    RECT 0 20.190 0.070 20.270 ;
    RECT 0 20.470 0.070 20.550 ;
    RECT 0 20.750 0.070 20.830 ;
    RECT 0 21.030 0.070 21.110 ;
    RECT 0 21.310 0.070 21.390 ;
    RECT 0 21.590 0.070 21.670 ;
    RECT 0 21.870 0.070 21.950 ;
    RECT 0 22.150 0.070 22.230 ;
    RECT 0 22.430 0.070 22.510 ;
    RECT 0 22.710 0.070 22.790 ;
    RECT 0 22.990 0.070 23.070 ;
    RECT 0 23.270 0.070 23.350 ;
    RECT 0 23.550 0.070 23.630 ;
    RECT 0 23.830 0.070 23.910 ;
    RECT 0 24.110 0.070 24.190 ;
    RECT 0 24.390 0.070 24.470 ;
    RECT 0 24.670 0.070 24.750 ;
    RECT 0 24.950 0.070 25.030 ;
    RECT 0 25.230 0.070 25.310 ;
    RECT 0 25.510 0.070 25.590 ;
    RECT 0 25.790 0.070 25.870 ;
    RECT 0 26.070 0.070 26.150 ;
    RECT 0 26.350 0.070 26.430 ;
    RECT 0 26.630 0.070 26.710 ;
    RECT 0 26.910 0.070 26.990 ;
    RECT 0 27.190 0.070 27.270 ;
    RECT 0 27.470 0.070 27.550 ;
    RECT 0 27.750 0.070 27.830 ;
    RECT 0 28.030 0.070 28.110 ;
    RECT 0 28.310 0.070 28.390 ;
    RECT 0 28.590 0.070 28.670 ;
    RECT 0 28.870 0.070 28.950 ;
    RECT 0 29.150 0.070 29.230 ;
    RECT 0 29.430 0.070 29.510 ;
    RECT 0 29.710 0.070 29.790 ;
    RECT 0 29.990 0.070 30.070 ;
    RECT 0 30.270 0.070 30.350 ;
    RECT 0 30.550 0.070 30.630 ;
    RECT 0 30.830 0.070 30.910 ;
    RECT 0 31.110 0.070 31.190 ;
    RECT 0 31.390 0.070 31.470 ;
    RECT 0 31.670 0.070 31.750 ;
    RECT 0 31.950 0.070 32.030 ;
    RECT 0 32.230 0.070 32.310 ;
    RECT 0 32.510 0.070 32.590 ;
    RECT 0 32.790 0.070 32.870 ;
    RECT 0 33.070 0.070 33.150 ;
    RECT 0 33.350 0.070 33.430 ;
    RECT 0 33.630 0.070 33.710 ;
    RECT 0 33.910 0.070 33.990 ;
    RECT 0 34.190 0.070 34.270 ;
    RECT 0 34.470 0.070 34.550 ;
    RECT 0 34.750 0.070 34.830 ;
    RECT 0 35.030 0.070 35.110 ;
    RECT 0 35.310 0.070 35.390 ;
    RECT 0 35.590 0.070 35.670 ;
    RECT 0 35.870 0.070 35.950 ;
    RECT 0 36.150 0.070 36.230 ;
    RECT 0 36.430 0.070 36.510 ;
    RECT 0 36.710 0.070 36.790 ;
    RECT 0 36.990 0.070 37.070 ;
    RECT 0 37.270 0.070 37.350 ;
    RECT 0 37.550 0.070 37.630 ;
    RECT 0 37.830 0.070 38.750 ;
    RECT 0 38.950 0.070 39.030 ;
    RECT 0 39.230 0.070 39.310 ;
    RECT 0 39.510 0.070 39.590 ;
    RECT 0 39.790 0.070 39.870 ;
    RECT 0 40.070 0.070 40.150 ;
    RECT 0 40.350 0.070 40.430 ;
    RECT 0 40.630 0.070 40.710 ;
    RECT 0 40.910 0.070 40.990 ;
    RECT 0 41.190 0.070 41.270 ;
    RECT 0 41.470 0.070 41.550 ;
    RECT 0 41.750 0.070 41.830 ;
    RECT 0 42.030 0.070 42.110 ;
    RECT 0 42.310 0.070 42.390 ;
    RECT 0 42.590 0.070 42.670 ;
    RECT 0 42.870 0.070 42.950 ;
    RECT 0 43.150 0.070 43.230 ;
    RECT 0 43.430 0.070 43.510 ;
    RECT 0 43.710 0.070 43.790 ;
    RECT 0 43.990 0.070 44.070 ;
    RECT 0 44.270 0.070 44.350 ;
    RECT 0 44.550 0.070 44.630 ;
    RECT 0 44.830 0.070 44.910 ;
    RECT 0 45.110 0.070 45.190 ;
    RECT 0 45.390 0.070 45.470 ;
    RECT 0 45.670 0.070 45.750 ;
    RECT 0 45.950 0.070 46.030 ;
    RECT 0 46.230 0.070 46.310 ;
    RECT 0 46.510 0.070 46.590 ;
    RECT 0 46.790 0.070 46.870 ;
    RECT 0 47.070 0.070 47.150 ;
    RECT 0 47.350 0.070 47.430 ;
    RECT 0 47.630 0.070 47.710 ;
    RECT 0 47.910 0.070 47.990 ;
    RECT 0 48.190 0.070 48.270 ;
    RECT 0 48.470 0.070 48.550 ;
    RECT 0 48.750 0.070 48.830 ;
    RECT 0 49.030 0.070 49.110 ;
    RECT 0 49.310 0.070 49.390 ;
    RECT 0 49.590 0.070 49.670 ;
    RECT 0 49.870 0.070 49.950 ;
    RECT 0 50.150 0.070 50.230 ;
    RECT 0 50.430 0.070 50.510 ;
    RECT 0 50.710 0.070 50.790 ;
    RECT 0 50.990 0.070 51.070 ;
    RECT 0 51.270 0.070 51.350 ;
    RECT 0 51.550 0.070 51.630 ;
    RECT 0 51.830 0.070 51.910 ;
    RECT 0 52.110 0.070 52.190 ;
    RECT 0 52.390 0.070 52.470 ;
    RECT 0 52.670 0.070 52.750 ;
    RECT 0 52.950 0.070 53.030 ;
    RECT 0 53.230 0.070 53.310 ;
    RECT 0 53.510 0.070 53.590 ;
    RECT 0 53.790 0.070 53.870 ;
    RECT 0 54.070 0.070 54.150 ;
    RECT 0 54.350 0.070 54.430 ;
    RECT 0 54.630 0.070 54.710 ;
    RECT 0 54.910 0.070 54.990 ;
    RECT 0 55.190 0.070 55.270 ;
    RECT 0 55.470 0.070 55.550 ;
    RECT 0 55.750 0.070 55.830 ;
    RECT 0 56.030 0.070 56.110 ;
    RECT 0 56.310 0.070 56.390 ;
    RECT 0 56.590 0.070 56.670 ;
    RECT 0 56.870 0.070 56.950 ;
    RECT 0 57.150 0.070 57.230 ;
    RECT 0 57.430 0.070 57.510 ;
    RECT 0 57.710 0.070 57.790 ;
    RECT 0 57.990 0.070 58.070 ;
    RECT 0 58.270 0.070 58.350 ;
    RECT 0 58.550 0.070 58.630 ;
    RECT 0 58.830 0.070 58.910 ;
    RECT 0 59.110 0.070 59.190 ;
    RECT 0 59.390 0.070 59.470 ;
    RECT 0 59.670 0.070 59.750 ;
    RECT 0 59.950 0.070 60.030 ;
    RECT 0 60.230 0.070 60.310 ;
    RECT 0 60.510 0.070 60.590 ;
    RECT 0 60.790 0.070 60.870 ;
    RECT 0 61.070 0.070 61.150 ;
    RECT 0 61.350 0.070 61.430 ;
    RECT 0 61.630 0.070 61.710 ;
    RECT 0 61.910 0.070 61.990 ;
    RECT 0 62.190 0.070 62.270 ;
    RECT 0 62.470 0.070 62.550 ;
    RECT 0 62.750 0.070 62.830 ;
    RECT 0 63.030 0.070 63.110 ;
    RECT 0 63.310 0.070 63.390 ;
    RECT 0 63.590 0.070 63.670 ;
    RECT 0 63.870 0.070 63.950 ;
    RECT 0 64.150 0.070 64.230 ;
    RECT 0 64.430 0.070 64.510 ;
    RECT 0 64.710 0.070 64.790 ;
    RECT 0 64.990 0.070 65.070 ;
    RECT 0 65.270 0.070 65.350 ;
    RECT 0 65.550 0.070 65.630 ;
    RECT 0 65.830 0.070 65.910 ;
    RECT 0 66.110 0.070 66.190 ;
    RECT 0 66.390 0.070 66.470 ;
    RECT 0 66.670 0.070 66.750 ;
    RECT 0 66.950 0.070 67.030 ;
    RECT 0 67.230 0.070 67.310 ;
    RECT 0 67.510 0.070 67.590 ;
    RECT 0 67.790 0.070 67.870 ;
    RECT 0 68.070 0.070 68.150 ;
    RECT 0 68.350 0.070 68.430 ;
    RECT 0 68.630 0.070 68.710 ;
    RECT 0 68.910 0.070 68.990 ;
    RECT 0 69.190 0.070 69.270 ;
    RECT 0 69.470 0.070 69.550 ;
    RECT 0 69.750 0.070 69.830 ;
    RECT 0 70.030 0.070 70.110 ;
    RECT 0 70.310 0.070 70.390 ;
    RECT 0 70.590 0.070 70.670 ;
    RECT 0 70.870 0.070 70.950 ;
    RECT 0 71.150 0.070 71.230 ;
    RECT 0 71.430 0.070 71.510 ;
    RECT 0 71.710 0.070 71.790 ;
    RECT 0 71.990 0.070 72.070 ;
    RECT 0 72.270 0.070 72.350 ;
    RECT 0 72.550 0.070 72.630 ;
    RECT 0 72.830 0.070 72.910 ;
    RECT 0 73.110 0.070 73.190 ;
    RECT 0 73.390 0.070 73.470 ;
    RECT 0 73.670 0.070 73.750 ;
    RECT 0 73.950 0.070 74.030 ;
    RECT 0 74.230 0.070 74.310 ;
    RECT 0 74.510 0.070 75.430 ;
    RECT 0 75.630 0.070 75.710 ;
    RECT 0 75.910 0.070 75.990 ;
    RECT 0 76.190 0.070 76.270 ;
    RECT 0 76.470 0.070 76.550 ;
    RECT 0 76.750 0.070 76.830 ;
    RECT 0 77.030 0.070 77.110 ;
    RECT 0 77.310 0.070 77.390 ;
    RECT 0 77.590 0.070 77.670 ;
    RECT 0 77.870 0.070 77.950 ;
    RECT 0 78.150 0.070 78.230 ;
    RECT 0 78.430 0.070 78.510 ;
    RECT 0 78.710 0.070 78.790 ;
    RECT 0 78.990 0.070 79.070 ;
    RECT 0 79.270 0.070 79.350 ;
    RECT 0 79.550 0.070 79.630 ;
    RECT 0 79.830 0.070 79.910 ;
    RECT 0 80.110 0.070 80.190 ;
    RECT 0 80.390 0.070 80.470 ;
    RECT 0 80.670 0.070 80.750 ;
    RECT 0 80.950 0.070 81.030 ;
    RECT 0 81.230 0.070 81.310 ;
    RECT 0 81.510 0.070 81.590 ;
    RECT 0 81.790 0.070 81.870 ;
    RECT 0 82.070 0.070 82.150 ;
    RECT 0 82.350 0.070 82.430 ;
    RECT 0 82.630 0.070 82.710 ;
    RECT 0 82.910 0.070 82.990 ;
    RECT 0 83.190 0.070 83.270 ;
    RECT 0 83.470 0.070 83.550 ;
    RECT 0 83.750 0.070 83.830 ;
    RECT 0 84.030 0.070 84.110 ;
    RECT 0 84.310 0.070 84.390 ;
    RECT 0 84.590 0.070 84.670 ;
    RECT 0 84.870 0.070 84.950 ;
    RECT 0 85.150 0.070 85.230 ;
    RECT 0 85.430 0.070 85.510 ;
    RECT 0 85.710 0.070 85.790 ;
    RECT 0 85.990 0.070 86.070 ;
    RECT 0 86.270 0.070 86.350 ;
    RECT 0 86.550 0.070 86.630 ;
    RECT 0 86.830 0.070 86.910 ;
    RECT 0 87.110 0.070 87.190 ;
    RECT 0 87.390 0.070 87.470 ;
    RECT 0 87.670 0.070 87.750 ;
    RECT 0 87.950 0.070 88.030 ;
    RECT 0 88.230 0.070 88.310 ;
    RECT 0 88.510 0.070 88.590 ;
    RECT 0 88.790 0.070 88.870 ;
    RECT 0 89.070 0.070 89.150 ;
    RECT 0 89.350 0.070 89.430 ;
    RECT 0 89.630 0.070 89.710 ;
    RECT 0 89.910 0.070 89.990 ;
    RECT 0 90.190 0.070 90.270 ;
    RECT 0 90.470 0.070 90.550 ;
    RECT 0 90.750 0.070 90.830 ;
    RECT 0 91.030 0.070 91.110 ;
    RECT 0 91.310 0.070 91.390 ;
    RECT 0 91.590 0.070 91.670 ;
    RECT 0 91.870 0.070 91.950 ;
    RECT 0 92.150 0.070 92.230 ;
    RECT 0 92.430 0.070 92.510 ;
    RECT 0 92.710 0.070 92.790 ;
    RECT 0 92.990 0.070 93.070 ;
    RECT 0 93.270 0.070 93.350 ;
    RECT 0 93.550 0.070 93.630 ;
    RECT 0 93.830 0.070 93.910 ;
    RECT 0 94.110 0.070 94.190 ;
    RECT 0 94.390 0.070 94.470 ;
    RECT 0 94.670 0.070 94.750 ;
    RECT 0 94.950 0.070 95.030 ;
    RECT 0 95.230 0.070 95.310 ;
    RECT 0 95.510 0.070 95.590 ;
    RECT 0 95.790 0.070 95.870 ;
    RECT 0 96.070 0.070 96.150 ;
    RECT 0 96.350 0.070 96.430 ;
    RECT 0 96.630 0.070 96.710 ;
    RECT 0 96.910 0.070 96.990 ;
    RECT 0 97.190 0.070 97.270 ;
    RECT 0 97.470 0.070 97.550 ;
    RECT 0 97.750 0.070 97.830 ;
    RECT 0 98.030 0.070 98.110 ;
    RECT 0 98.310 0.070 98.390 ;
    RECT 0 98.590 0.070 98.670 ;
    RECT 0 98.870 0.070 98.950 ;
    RECT 0 99.150 0.070 99.230 ;
    RECT 0 99.430 0.070 99.510 ;
    RECT 0 99.710 0.070 99.790 ;
    RECT 0 99.990 0.070 100.070 ;
    RECT 0 100.270 0.070 100.350 ;
    RECT 0 100.550 0.070 100.630 ;
    RECT 0 100.830 0.070 100.910 ;
    RECT 0 101.110 0.070 101.190 ;
    RECT 0 101.390 0.070 101.470 ;
    RECT 0 101.670 0.070 101.750 ;
    RECT 0 101.950 0.070 102.030 ;
    RECT 0 102.230 0.070 102.310 ;
    RECT 0 102.510 0.070 102.590 ;
    RECT 0 102.790 0.070 102.870 ;
    RECT 0 103.070 0.070 103.150 ;
    RECT 0 103.350 0.070 103.430 ;
    RECT 0 103.630 0.070 103.710 ;
    RECT 0 103.910 0.070 103.990 ;
    RECT 0 104.190 0.070 104.270 ;
    RECT 0 104.470 0.070 104.550 ;
    RECT 0 104.750 0.070 104.830 ;
    RECT 0 105.030 0.070 105.110 ;
    RECT 0 105.310 0.070 105.390 ;
    RECT 0 105.590 0.070 105.670 ;
    RECT 0 105.870 0.070 105.950 ;
    RECT 0 106.150 0.070 106.230 ;
    RECT 0 106.430 0.070 106.510 ;
    RECT 0 106.710 0.070 106.790 ;
    RECT 0 106.990 0.070 107.070 ;
    RECT 0 107.270 0.070 107.350 ;
    RECT 0 107.550 0.070 107.630 ;
    RECT 0 107.830 0.070 107.910 ;
    RECT 0 108.110 0.070 108.190 ;
    RECT 0 108.390 0.070 108.470 ;
    RECT 0 108.670 0.070 108.750 ;
    RECT 0 108.950 0.070 109.030 ;
    RECT 0 109.230 0.070 109.310 ;
    RECT 0 109.510 0.070 109.590 ;
    RECT 0 109.790 0.070 109.870 ;
    RECT 0 110.070 0.070 110.150 ;
    RECT 0 110.350 0.070 110.430 ;
    RECT 0 110.630 0.070 110.710 ;
    RECT 0 110.910 0.070 110.990 ;
    RECT 0 111.190 0.070 112.110 ;
    RECT 0 112.310 0.070 112.390 ;
    RECT 0 112.590 0.070 112.670 ;
    RECT 0 112.870 0.070 112.950 ;
    RECT 0 113.150 0.070 113.230 ;
    RECT 0 113.430 0.070 113.510 ;
    RECT 0 113.710 0.070 113.790 ;
    RECT 0 113.990 0.070 114.070 ;
    RECT 0 114.270 0.070 114.350 ;
    RECT 0 114.550 0.070 114.630 ;
    RECT 0 114.830 0.070 114.910 ;
    RECT 0 115.110 0.070 115.190 ;
    RECT 0 115.390 0.070 115.470 ;
    RECT 0 115.670 0.070 115.750 ;
    RECT 0 115.950 0.070 116.030 ;
    RECT 0 116.230 0.070 116.310 ;
    RECT 0 116.510 0.070 760.200 ;
    LAYER metal4 ;
    RECT 0 0 760.000 2.100 ;
    RECT 0 758.100 760.000 760.200 ;
    RECT 0.000 2.100 1.960 758.100 ;
    RECT 2.240 2.100 3.640 758.100 ;
    RECT 3.920 2.100 5.320 758.100 ;
    RECT 5.600 2.100 7.000 758.100 ;
    RECT 7.280 2.100 8.680 758.100 ;
    RECT 8.960 2.100 10.360 758.100 ;
    RECT 10.640 2.100 12.040 758.100 ;
    RECT 12.320 2.100 13.720 758.100 ;
    RECT 14.000 2.100 15.400 758.100 ;
    RECT 15.680 2.100 17.080 758.100 ;
    RECT 17.360 2.100 18.760 758.100 ;
    RECT 19.040 2.100 20.440 758.100 ;
    RECT 20.720 2.100 22.120 758.100 ;
    RECT 22.400 2.100 23.800 758.100 ;
    RECT 24.080 2.100 25.480 758.100 ;
    RECT 25.760 2.100 27.160 758.100 ;
    RECT 27.440 2.100 28.840 758.100 ;
    RECT 29.120 2.100 30.520 758.100 ;
    RECT 30.800 2.100 32.200 758.100 ;
    RECT 32.480 2.100 33.880 758.100 ;
    RECT 34.160 2.100 35.560 758.100 ;
    RECT 35.840 2.100 37.240 758.100 ;
    RECT 37.520 2.100 38.920 758.100 ;
    RECT 39.200 2.100 40.600 758.100 ;
    RECT 40.880 2.100 42.280 758.100 ;
    RECT 42.560 2.100 43.960 758.100 ;
    RECT 44.240 2.100 45.640 758.100 ;
    RECT 45.920 2.100 47.320 758.100 ;
    RECT 47.600 2.100 49.000 758.100 ;
    RECT 49.280 2.100 50.680 758.100 ;
    RECT 50.960 2.100 52.360 758.100 ;
    RECT 52.640 2.100 54.040 758.100 ;
    RECT 54.320 2.100 55.720 758.100 ;
    RECT 56.000 2.100 57.400 758.100 ;
    RECT 57.680 2.100 59.080 758.100 ;
    RECT 59.360 2.100 60.760 758.100 ;
    RECT 61.040 2.100 62.440 758.100 ;
    RECT 62.720 2.100 64.120 758.100 ;
    RECT 64.400 2.100 65.800 758.100 ;
    RECT 66.080 2.100 67.480 758.100 ;
    RECT 67.760 2.100 69.160 758.100 ;
    RECT 69.440 2.100 70.840 758.100 ;
    RECT 71.120 2.100 72.520 758.100 ;
    RECT 72.800 2.100 74.200 758.100 ;
    RECT 74.480 2.100 75.880 758.100 ;
    RECT 76.160 2.100 77.560 758.100 ;
    RECT 77.840 2.100 79.240 758.100 ;
    RECT 79.520 2.100 80.920 758.100 ;
    RECT 81.200 2.100 82.600 758.100 ;
    RECT 82.880 2.100 84.280 758.100 ;
    RECT 84.560 2.100 85.960 758.100 ;
    RECT 86.240 2.100 87.640 758.100 ;
    RECT 87.920 2.100 89.320 758.100 ;
    RECT 89.600 2.100 91.000 758.100 ;
    RECT 91.280 2.100 92.680 758.100 ;
    RECT 92.960 2.100 94.360 758.100 ;
    RECT 94.640 2.100 96.040 758.100 ;
    RECT 96.320 2.100 97.720 758.100 ;
    RECT 98.000 2.100 99.400 758.100 ;
    RECT 99.680 2.100 101.080 758.100 ;
    RECT 101.360 2.100 102.760 758.100 ;
    RECT 103.040 2.100 104.440 758.100 ;
    RECT 104.720 2.100 106.120 758.100 ;
    RECT 106.400 2.100 107.800 758.100 ;
    RECT 108.080 2.100 109.480 758.100 ;
    RECT 109.760 2.100 111.160 758.100 ;
    RECT 111.440 2.100 112.840 758.100 ;
    RECT 113.120 2.100 114.520 758.100 ;
    RECT 114.800 2.100 116.200 758.100 ;
    RECT 116.480 2.100 117.880 758.100 ;
    RECT 118.160 2.100 119.560 758.100 ;
    RECT 119.840 2.100 121.240 758.100 ;
    RECT 121.520 2.100 122.920 758.100 ;
    RECT 123.200 2.100 124.600 758.100 ;
    RECT 124.880 2.100 126.280 758.100 ;
    RECT 126.560 2.100 127.960 758.100 ;
    RECT 128.240 2.100 129.640 758.100 ;
    RECT 129.920 2.100 131.320 758.100 ;
    RECT 131.600 2.100 133.000 758.100 ;
    RECT 133.280 2.100 134.680 758.100 ;
    RECT 134.960 2.100 136.360 758.100 ;
    RECT 136.640 2.100 138.040 758.100 ;
    RECT 138.320 2.100 139.720 758.100 ;
    RECT 140.000 2.100 141.400 758.100 ;
    RECT 141.680 2.100 143.080 758.100 ;
    RECT 143.360 2.100 144.760 758.100 ;
    RECT 145.040 2.100 146.440 758.100 ;
    RECT 146.720 2.100 148.120 758.100 ;
    RECT 148.400 2.100 149.800 758.100 ;
    RECT 150.080 2.100 151.480 758.100 ;
    RECT 151.760 2.100 153.160 758.100 ;
    RECT 153.440 2.100 154.840 758.100 ;
    RECT 155.120 2.100 156.520 758.100 ;
    RECT 156.800 2.100 158.200 758.100 ;
    RECT 158.480 2.100 159.880 758.100 ;
    RECT 160.160 2.100 161.560 758.100 ;
    RECT 161.840 2.100 163.240 758.100 ;
    RECT 163.520 2.100 164.920 758.100 ;
    RECT 165.200 2.100 166.600 758.100 ;
    RECT 166.880 2.100 168.280 758.100 ;
    RECT 168.560 2.100 169.960 758.100 ;
    RECT 170.240 2.100 171.640 758.100 ;
    RECT 171.920 2.100 173.320 758.100 ;
    RECT 173.600 2.100 175.000 758.100 ;
    RECT 175.280 2.100 176.680 758.100 ;
    RECT 176.960 2.100 178.360 758.100 ;
    RECT 178.640 2.100 180.040 758.100 ;
    RECT 180.320 2.100 181.720 758.100 ;
    RECT 182.000 2.100 183.400 758.100 ;
    RECT 183.680 2.100 185.080 758.100 ;
    RECT 185.360 2.100 186.760 758.100 ;
    RECT 187.040 2.100 188.440 758.100 ;
    RECT 188.720 2.100 190.120 758.100 ;
    RECT 190.400 2.100 191.800 758.100 ;
    RECT 192.080 2.100 193.480 758.100 ;
    RECT 193.760 2.100 195.160 758.100 ;
    RECT 195.440 2.100 196.840 758.100 ;
    RECT 197.120 2.100 198.520 758.100 ;
    RECT 198.800 2.100 200.200 758.100 ;
    RECT 200.480 2.100 201.880 758.100 ;
    RECT 202.160 2.100 203.560 758.100 ;
    RECT 203.840 2.100 205.240 758.100 ;
    RECT 205.520 2.100 206.920 758.100 ;
    RECT 207.200 2.100 208.600 758.100 ;
    RECT 208.880 2.100 210.280 758.100 ;
    RECT 210.560 2.100 211.960 758.100 ;
    RECT 212.240 2.100 213.640 758.100 ;
    RECT 213.920 2.100 215.320 758.100 ;
    RECT 215.600 2.100 217.000 758.100 ;
    RECT 217.280 2.100 218.680 758.100 ;
    RECT 218.960 2.100 220.360 758.100 ;
    RECT 220.640 2.100 222.040 758.100 ;
    RECT 222.320 2.100 223.720 758.100 ;
    RECT 224.000 2.100 225.400 758.100 ;
    RECT 225.680 2.100 227.080 758.100 ;
    RECT 227.360 2.100 228.760 758.100 ;
    RECT 229.040 2.100 230.440 758.100 ;
    RECT 230.720 2.100 232.120 758.100 ;
    RECT 232.400 2.100 233.800 758.100 ;
    RECT 234.080 2.100 235.480 758.100 ;
    RECT 235.760 2.100 237.160 758.100 ;
    RECT 237.440 2.100 238.840 758.100 ;
    RECT 239.120 2.100 240.520 758.100 ;
    RECT 240.800 2.100 242.200 758.100 ;
    RECT 242.480 2.100 243.880 758.100 ;
    RECT 244.160 2.100 245.560 758.100 ;
    RECT 245.840 2.100 247.240 758.100 ;
    RECT 247.520 2.100 248.920 758.100 ;
    RECT 249.200 2.100 250.600 758.100 ;
    RECT 250.880 2.100 252.280 758.100 ;
    RECT 252.560 2.100 253.960 758.100 ;
    RECT 254.240 2.100 255.640 758.100 ;
    RECT 255.920 2.100 257.320 758.100 ;
    RECT 257.600 2.100 259.000 758.100 ;
    RECT 259.280 2.100 260.680 758.100 ;
    RECT 260.960 2.100 262.360 758.100 ;
    RECT 262.640 2.100 264.040 758.100 ;
    RECT 264.320 2.100 265.720 758.100 ;
    RECT 266.000 2.100 267.400 758.100 ;
    RECT 267.680 2.100 269.080 758.100 ;
    RECT 269.360 2.100 270.760 758.100 ;
    RECT 271.040 2.100 272.440 758.100 ;
    RECT 272.720 2.100 274.120 758.100 ;
    RECT 274.400 2.100 275.800 758.100 ;
    RECT 276.080 2.100 277.480 758.100 ;
    RECT 277.760 2.100 279.160 758.100 ;
    RECT 279.440 2.100 280.840 758.100 ;
    RECT 281.120 2.100 282.520 758.100 ;
    RECT 282.800 2.100 284.200 758.100 ;
    RECT 284.480 2.100 285.880 758.100 ;
    RECT 286.160 2.100 287.560 758.100 ;
    RECT 287.840 2.100 289.240 758.100 ;
    RECT 289.520 2.100 290.920 758.100 ;
    RECT 291.200 2.100 292.600 758.100 ;
    RECT 292.880 2.100 294.280 758.100 ;
    RECT 294.560 2.100 295.960 758.100 ;
    RECT 296.240 2.100 297.640 758.100 ;
    RECT 297.920 2.100 299.320 758.100 ;
    RECT 299.600 2.100 301.000 758.100 ;
    RECT 301.280 2.100 302.680 758.100 ;
    RECT 302.960 2.100 304.360 758.100 ;
    RECT 304.640 2.100 306.040 758.100 ;
    RECT 306.320 2.100 307.720 758.100 ;
    RECT 308.000 2.100 309.400 758.100 ;
    RECT 309.680 2.100 311.080 758.100 ;
    RECT 311.360 2.100 312.760 758.100 ;
    RECT 313.040 2.100 314.440 758.100 ;
    RECT 314.720 2.100 316.120 758.100 ;
    RECT 316.400 2.100 317.800 758.100 ;
    RECT 318.080 2.100 319.480 758.100 ;
    RECT 319.760 2.100 321.160 758.100 ;
    RECT 321.440 2.100 322.840 758.100 ;
    RECT 323.120 2.100 324.520 758.100 ;
    RECT 324.800 2.100 326.200 758.100 ;
    RECT 326.480 2.100 327.880 758.100 ;
    RECT 328.160 2.100 329.560 758.100 ;
    RECT 329.840 2.100 331.240 758.100 ;
    RECT 331.520 2.100 332.920 758.100 ;
    RECT 333.200 2.100 334.600 758.100 ;
    RECT 334.880 2.100 336.280 758.100 ;
    RECT 336.560 2.100 337.960 758.100 ;
    RECT 338.240 2.100 339.640 758.100 ;
    RECT 339.920 2.100 341.320 758.100 ;
    RECT 341.600 2.100 343.000 758.100 ;
    RECT 343.280 2.100 344.680 758.100 ;
    RECT 344.960 2.100 346.360 758.100 ;
    RECT 346.640 2.100 348.040 758.100 ;
    RECT 348.320 2.100 349.720 758.100 ;
    RECT 350.000 2.100 351.400 758.100 ;
    RECT 351.680 2.100 353.080 758.100 ;
    RECT 353.360 2.100 354.760 758.100 ;
    RECT 355.040 2.100 356.440 758.100 ;
    RECT 356.720 2.100 358.120 758.100 ;
    RECT 358.400 2.100 359.800 758.100 ;
    RECT 360.080 2.100 361.480 758.100 ;
    RECT 361.760 2.100 363.160 758.100 ;
    RECT 363.440 2.100 364.840 758.100 ;
    RECT 365.120 2.100 366.520 758.100 ;
    RECT 366.800 2.100 368.200 758.100 ;
    RECT 368.480 2.100 369.880 758.100 ;
    RECT 370.160 2.100 371.560 758.100 ;
    RECT 371.840 2.100 373.240 758.100 ;
    RECT 373.520 2.100 374.920 758.100 ;
    RECT 375.200 2.100 376.600 758.100 ;
    RECT 376.880 2.100 378.280 758.100 ;
    RECT 378.560 2.100 379.960 758.100 ;
    RECT 380.240 2.100 381.640 758.100 ;
    RECT 381.920 2.100 383.320 758.100 ;
    RECT 383.600 2.100 385.000 758.100 ;
    RECT 385.280 2.100 386.680 758.100 ;
    RECT 386.960 2.100 388.360 758.100 ;
    RECT 388.640 2.100 390.040 758.100 ;
    RECT 390.320 2.100 391.720 758.100 ;
    RECT 392.000 2.100 393.400 758.100 ;
    RECT 393.680 2.100 395.080 758.100 ;
    RECT 395.360 2.100 396.760 758.100 ;
    RECT 397.040 2.100 398.440 758.100 ;
    RECT 398.720 2.100 400.120 758.100 ;
    RECT 400.400 2.100 401.800 758.100 ;
    RECT 402.080 2.100 403.480 758.100 ;
    RECT 403.760 2.100 405.160 758.100 ;
    RECT 405.440 2.100 406.840 758.100 ;
    RECT 407.120 2.100 408.520 758.100 ;
    RECT 408.800 2.100 410.200 758.100 ;
    RECT 410.480 2.100 411.880 758.100 ;
    RECT 412.160 2.100 413.560 758.100 ;
    RECT 413.840 2.100 415.240 758.100 ;
    RECT 415.520 2.100 416.920 758.100 ;
    RECT 417.200 2.100 418.600 758.100 ;
    RECT 418.880 2.100 420.280 758.100 ;
    RECT 420.560 2.100 421.960 758.100 ;
    RECT 422.240 2.100 423.640 758.100 ;
    RECT 423.920 2.100 425.320 758.100 ;
    RECT 425.600 2.100 427.000 758.100 ;
    RECT 427.280 2.100 428.680 758.100 ;
    RECT 428.960 2.100 430.360 758.100 ;
    RECT 430.640 2.100 432.040 758.100 ;
    RECT 432.320 2.100 433.720 758.100 ;
    RECT 434.000 2.100 435.400 758.100 ;
    RECT 435.680 2.100 437.080 758.100 ;
    RECT 437.360 2.100 438.760 758.100 ;
    RECT 439.040 2.100 440.440 758.100 ;
    RECT 440.720 2.100 442.120 758.100 ;
    RECT 442.400 2.100 443.800 758.100 ;
    RECT 444.080 2.100 445.480 758.100 ;
    RECT 445.760 2.100 447.160 758.100 ;
    RECT 447.440 2.100 448.840 758.100 ;
    RECT 449.120 2.100 450.520 758.100 ;
    RECT 450.800 2.100 452.200 758.100 ;
    RECT 452.480 2.100 453.880 758.100 ;
    RECT 454.160 2.100 455.560 758.100 ;
    RECT 455.840 2.100 457.240 758.100 ;
    RECT 457.520 2.100 458.920 758.100 ;
    RECT 459.200 2.100 460.600 758.100 ;
    RECT 460.880 2.100 462.280 758.100 ;
    RECT 462.560 2.100 463.960 758.100 ;
    RECT 464.240 2.100 465.640 758.100 ;
    RECT 465.920 2.100 467.320 758.100 ;
    RECT 467.600 2.100 469.000 758.100 ;
    RECT 469.280 2.100 470.680 758.100 ;
    RECT 470.960 2.100 472.360 758.100 ;
    RECT 472.640 2.100 474.040 758.100 ;
    RECT 474.320 2.100 475.720 758.100 ;
    RECT 476.000 2.100 477.400 758.100 ;
    RECT 477.680 2.100 479.080 758.100 ;
    RECT 479.360 2.100 480.760 758.100 ;
    RECT 481.040 2.100 482.440 758.100 ;
    RECT 482.720 2.100 484.120 758.100 ;
    RECT 484.400 2.100 485.800 758.100 ;
    RECT 486.080 2.100 487.480 758.100 ;
    RECT 487.760 2.100 489.160 758.100 ;
    RECT 489.440 2.100 490.840 758.100 ;
    RECT 491.120 2.100 492.520 758.100 ;
    RECT 492.800 2.100 494.200 758.100 ;
    RECT 494.480 2.100 495.880 758.100 ;
    RECT 496.160 2.100 497.560 758.100 ;
    RECT 497.840 2.100 499.240 758.100 ;
    RECT 499.520 2.100 500.920 758.100 ;
    RECT 501.200 2.100 502.600 758.100 ;
    RECT 502.880 2.100 504.280 758.100 ;
    RECT 504.560 2.100 505.960 758.100 ;
    RECT 506.240 2.100 507.640 758.100 ;
    RECT 507.920 2.100 509.320 758.100 ;
    RECT 509.600 2.100 511.000 758.100 ;
    RECT 511.280 2.100 512.680 758.100 ;
    RECT 512.960 2.100 514.360 758.100 ;
    RECT 514.640 2.100 516.040 758.100 ;
    RECT 516.320 2.100 517.720 758.100 ;
    RECT 518.000 2.100 519.400 758.100 ;
    RECT 519.680 2.100 521.080 758.100 ;
    RECT 521.360 2.100 522.760 758.100 ;
    RECT 523.040 2.100 524.440 758.100 ;
    RECT 524.720 2.100 526.120 758.100 ;
    RECT 526.400 2.100 527.800 758.100 ;
    RECT 528.080 2.100 529.480 758.100 ;
    RECT 529.760 2.100 531.160 758.100 ;
    RECT 531.440 2.100 532.840 758.100 ;
    RECT 533.120 2.100 534.520 758.100 ;
    RECT 534.800 2.100 536.200 758.100 ;
    RECT 536.480 2.100 537.880 758.100 ;
    RECT 538.160 2.100 539.560 758.100 ;
    RECT 539.840 2.100 541.240 758.100 ;
    RECT 541.520 2.100 542.920 758.100 ;
    RECT 543.200 2.100 544.600 758.100 ;
    RECT 544.880 2.100 546.280 758.100 ;
    RECT 546.560 2.100 547.960 758.100 ;
    RECT 548.240 2.100 549.640 758.100 ;
    RECT 549.920 2.100 551.320 758.100 ;
    RECT 551.600 2.100 553.000 758.100 ;
    RECT 553.280 2.100 554.680 758.100 ;
    RECT 554.960 2.100 556.360 758.100 ;
    RECT 556.640 2.100 558.040 758.100 ;
    RECT 558.320 2.100 559.720 758.100 ;
    RECT 560.000 2.100 561.400 758.100 ;
    RECT 561.680 2.100 563.080 758.100 ;
    RECT 563.360 2.100 564.760 758.100 ;
    RECT 565.040 2.100 566.440 758.100 ;
    RECT 566.720 2.100 568.120 758.100 ;
    RECT 568.400 2.100 569.800 758.100 ;
    RECT 570.080 2.100 571.480 758.100 ;
    RECT 571.760 2.100 573.160 758.100 ;
    RECT 573.440 2.100 574.840 758.100 ;
    RECT 575.120 2.100 576.520 758.100 ;
    RECT 576.800 2.100 578.200 758.100 ;
    RECT 578.480 2.100 579.880 758.100 ;
    RECT 580.160 2.100 581.560 758.100 ;
    RECT 581.840 2.100 583.240 758.100 ;
    RECT 583.520 2.100 584.920 758.100 ;
    RECT 585.200 2.100 586.600 758.100 ;
    RECT 586.880 2.100 588.280 758.100 ;
    RECT 588.560 2.100 589.960 758.100 ;
    RECT 590.240 2.100 591.640 758.100 ;
    RECT 591.920 2.100 593.320 758.100 ;
    RECT 593.600 2.100 595.000 758.100 ;
    RECT 595.280 2.100 596.680 758.100 ;
    RECT 596.960 2.100 598.360 758.100 ;
    RECT 598.640 2.100 600.040 758.100 ;
    RECT 600.320 2.100 601.720 758.100 ;
    RECT 602.000 2.100 603.400 758.100 ;
    RECT 603.680 2.100 605.080 758.100 ;
    RECT 605.360 2.100 606.760 758.100 ;
    RECT 607.040 2.100 608.440 758.100 ;
    RECT 608.720 2.100 610.120 758.100 ;
    RECT 610.400 2.100 611.800 758.100 ;
    RECT 612.080 2.100 613.480 758.100 ;
    RECT 613.760 2.100 615.160 758.100 ;
    RECT 615.440 2.100 616.840 758.100 ;
    RECT 617.120 2.100 618.520 758.100 ;
    RECT 618.800 2.100 620.200 758.100 ;
    RECT 620.480 2.100 621.880 758.100 ;
    RECT 622.160 2.100 623.560 758.100 ;
    RECT 623.840 2.100 625.240 758.100 ;
    RECT 625.520 2.100 626.920 758.100 ;
    RECT 627.200 2.100 628.600 758.100 ;
    RECT 628.880 2.100 630.280 758.100 ;
    RECT 630.560 2.100 631.960 758.100 ;
    RECT 632.240 2.100 633.640 758.100 ;
    RECT 633.920 2.100 635.320 758.100 ;
    RECT 635.600 2.100 637.000 758.100 ;
    RECT 637.280 2.100 638.680 758.100 ;
    RECT 638.960 2.100 640.360 758.100 ;
    RECT 640.640 2.100 642.040 758.100 ;
    RECT 642.320 2.100 643.720 758.100 ;
    RECT 644.000 2.100 645.400 758.100 ;
    RECT 645.680 2.100 647.080 758.100 ;
    RECT 647.360 2.100 648.760 758.100 ;
    RECT 649.040 2.100 650.440 758.100 ;
    RECT 650.720 2.100 652.120 758.100 ;
    RECT 652.400 2.100 653.800 758.100 ;
    RECT 654.080 2.100 655.480 758.100 ;
    RECT 655.760 2.100 657.160 758.100 ;
    RECT 657.440 2.100 658.840 758.100 ;
    RECT 659.120 2.100 660.520 758.100 ;
    RECT 660.800 2.100 662.200 758.100 ;
    RECT 662.480 2.100 663.880 758.100 ;
    RECT 664.160 2.100 665.560 758.100 ;
    RECT 665.840 2.100 667.240 758.100 ;
    RECT 667.520 2.100 668.920 758.100 ;
    RECT 669.200 2.100 670.600 758.100 ;
    RECT 670.880 2.100 672.280 758.100 ;
    RECT 672.560 2.100 673.960 758.100 ;
    RECT 674.240 2.100 675.640 758.100 ;
    RECT 675.920 2.100 677.320 758.100 ;
    RECT 677.600 2.100 679.000 758.100 ;
    RECT 679.280 2.100 680.680 758.100 ;
    RECT 680.960 2.100 682.360 758.100 ;
    RECT 682.640 2.100 684.040 758.100 ;
    RECT 684.320 2.100 685.720 758.100 ;
    RECT 686.000 2.100 687.400 758.100 ;
    RECT 687.680 2.100 689.080 758.100 ;
    RECT 689.360 2.100 690.760 758.100 ;
    RECT 691.040 2.100 692.440 758.100 ;
    RECT 692.720 2.100 694.120 758.100 ;
    RECT 694.400 2.100 695.800 758.100 ;
    RECT 696.080 2.100 697.480 758.100 ;
    RECT 697.760 2.100 699.160 758.100 ;
    RECT 699.440 2.100 700.840 758.100 ;
    RECT 701.120 2.100 702.520 758.100 ;
    RECT 702.800 2.100 704.200 758.100 ;
    RECT 704.480 2.100 705.880 758.100 ;
    RECT 706.160 2.100 707.560 758.100 ;
    RECT 707.840 2.100 709.240 758.100 ;
    RECT 709.520 2.100 710.920 758.100 ;
    RECT 711.200 2.100 712.600 758.100 ;
    RECT 712.880 2.100 714.280 758.100 ;
    RECT 714.560 2.100 715.960 758.100 ;
    RECT 716.240 2.100 717.640 758.100 ;
    RECT 717.920 2.100 719.320 758.100 ;
    RECT 719.600 2.100 721.000 758.100 ;
    RECT 721.280 2.100 722.680 758.100 ;
    RECT 722.960 2.100 724.360 758.100 ;
    RECT 724.640 2.100 726.040 758.100 ;
    RECT 726.320 2.100 727.720 758.100 ;
    RECT 728.000 2.100 729.400 758.100 ;
    RECT 729.680 2.100 731.080 758.100 ;
    RECT 731.360 2.100 732.760 758.100 ;
    RECT 733.040 2.100 734.440 758.100 ;
    RECT 734.720 2.100 736.120 758.100 ;
    RECT 736.400 2.100 737.800 758.100 ;
    RECT 738.080 2.100 739.480 758.100 ;
    RECT 739.760 2.100 741.160 758.100 ;
    RECT 741.440 2.100 742.840 758.100 ;
    RECT 743.120 2.100 744.520 758.100 ;
    RECT 744.800 2.100 746.200 758.100 ;
    RECT 746.480 2.100 747.880 758.100 ;
    RECT 748.160 2.100 749.560 758.100 ;
    RECT 749.840 2.100 751.240 758.100 ;
    RECT 751.520 2.100 752.920 758.100 ;
    RECT 753.200 2.100 754.600 758.100 ;
    RECT 754.880 2.100 756.280 758.100 ;
    RECT 756.560 2.100 760.000 758.100 ;
    LAYER OVERLAP ;
    RECT 0 0 760.000 760.200 ;
  END
END fakeram45_8192x128

END LIBRARY
